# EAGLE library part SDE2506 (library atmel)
I2C/MicroWire EEPROM (24xxx)

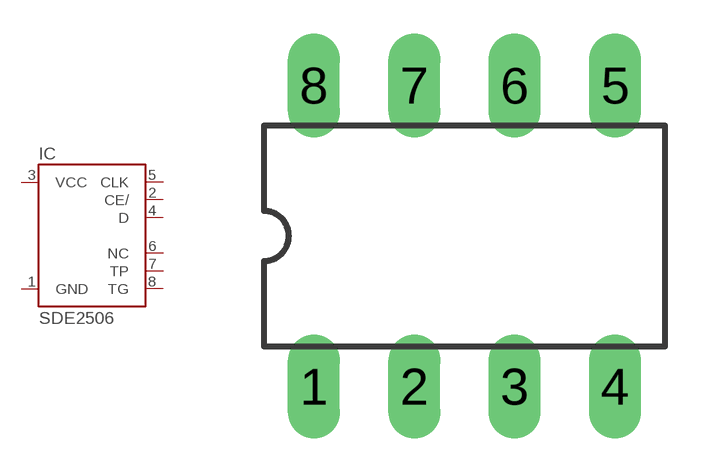
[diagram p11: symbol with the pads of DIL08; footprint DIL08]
Designator prefix IC

## SDE2506P (OC_FARNELL: unknown; OC_NEWARK: unknown)  [DIL08]
1  GND  pwr
2  CE/  in
3  VCC  pwr
4  D
5  CLK  in
6  NC  nc
7  TP  in
8  TG

## Footprint DIL08 (pad centres in mm)
Dual In Line
drill 0.813 long: 1 -3.81,-3.81; 2 -1.27,-3.81; 3 1.27,-3.81; 4 3.81,-3.81; 5 3.81,3.81; 6 1.27,3.81; 7 -1.27,3.81; 8 -3.81,3.81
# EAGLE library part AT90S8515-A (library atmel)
MICROCONTROLLER 8 Kbytes FLASH 512 bytes SRAM 512 bytes EEPROM UART

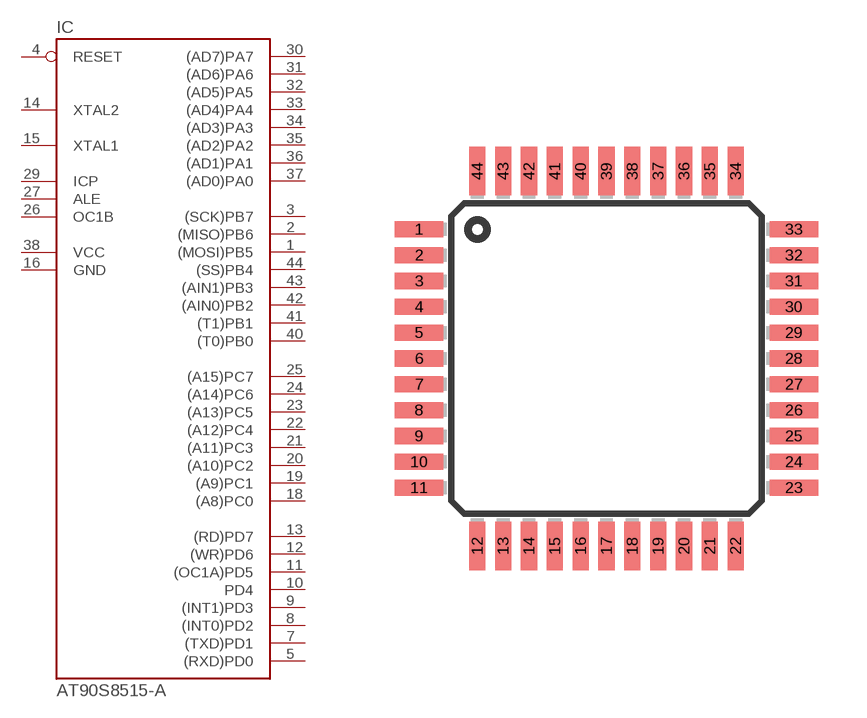
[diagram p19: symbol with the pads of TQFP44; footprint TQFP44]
Designator prefix IC

## AT90S8515-AA (OC_FARNELL: unknown; OC_NEWARK: unknown)  [TQFP44]
1  (MOSI)PB5
2  (MISO)PB6
3  (SCK)PB7
4  RESET  in
5  (RXD)PD0
6  NC1  nc
7  (TXD)PD1
8  (INT0)PD2
9  (INT1)PD3
10  PD4
11  (OC1A)PD5
12  (WR)PD6
13  (RD)PD7
14  XTAL2
15  XTAL1
16  GND  pwr
17  NC2  nc
18  (A8)PC0
19  (A9)PC1
20  (A10)PC2
21  (A11)PC3
22  (A12)PC4
23  (A13)PC5
24  (A14)PC6
25  (A15)PC7
26  OC1B
27  ALE
28  NC3  nc
29  ICP
30  (AD7)PA7
31  (AD6)PA6
32  (AD5)PA5
33  (AD4)PA4
34  (AD3)PA3
35  (AD2)PA2
36  (AD1)PA1
37  (AD0)PA0
38  VCC  pwr
39  NC4  nc
40  (T0)PB0
41  (T1)PB1
42  (AIN0)PB2
43  (AIN1)PB3
44  (SS)PB4

## Footprint TQFP44 (pad centres in mm)
44-lead Thin Quad Flat Package
smd 1.5 x 0.5: 1 -5.8,4; 2 -5.8,3.2; 3 -5.8,2.4; 4 -5.8,1.6; 5 -5.8,0.8; 6 -5.8,0; 7 -5.8,-0.8; 8 -5.8,-1.6; 9 -5.8,-2.4; 10 -5.8,-3.2; 11 -5.8,-4; 23 5.8,-4; 24 5.8,-3.2; 25 5.8,-2.4; 26 5.8,-1.6; 27 5.8,-0.8; 28 5.8,0; 29 5.8,0.8; 30 5.8,1.6; 31 5.8,2.4; 32 5.8,3.2; 33 5.8,4
smd 0.5 x 1.5: 12 -4,-5.8; 13 -3.2,-5.8; 14 -2.4,-5.8; 15 -1.6,-5.8; 16 -0.8,-5.8; 17 0,-5.8; 18 0.8,-5.8; 19 1.6,-5.8; 20 2.4,-5.8; 21 3.2,-5.8; 22 4,-5.8; 34 4,5.8; 35 3.2,5.8; 36 2.4,5.8; 37 1.6,5.8; 38 0.8,5.8; 39 0,5.8; 40 -0.8,5.8; 41 -1.6,5.8; 42 -2.4,5.8; 43 -3.2,5.8; 44 -4,5.8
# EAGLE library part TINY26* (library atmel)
8-bit AVR Microcontroller with 2K Bytes Flash Source: http://www.atmel.com .. doc1477.pdf

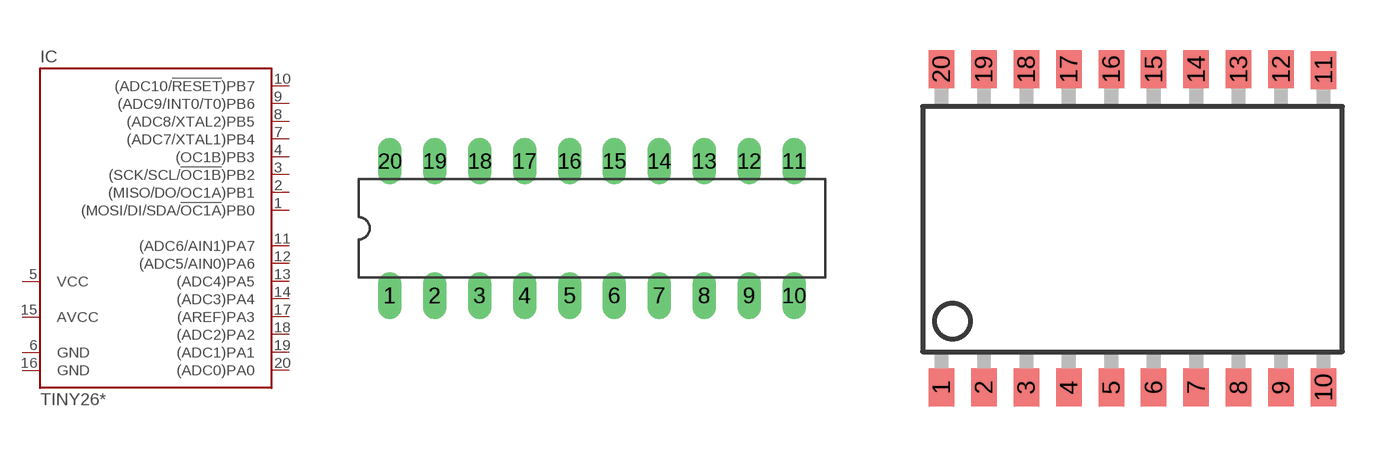
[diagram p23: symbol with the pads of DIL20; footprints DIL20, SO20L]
Designator prefix IC

## TINY26P (MPN: ATTINY261-20PU; OC_FARNELL: 1455146; OC_NEWARK: 58M3782), TINY26LP (MPN: ATTINY26L-8PU; OC_FARNELL: 9171657; OC_NEWARK: 01M6920)  [DIL20]
1  (MOSI/DI/SDA/!OC1A!)PB0
2  (MISO/DO/OC1A)PB1
3  (SCK/SCL/!OC1B!)PB2
4  (OC1B)PB3
5  VCC  pwr
6  GND  pwr
7  (ADC7/XTAL1)PB4
8  (ADC8/XTAL2)PB5
9  (ADC9/INT0/T0)PB6
10  (ADC10/!RESET!)PB7
11  (ADC6/AIN1)PA7
12  (ADC5/AIN0)PA6
13  (ADC4)PA5
14  (ADC3)PA4
15  AVCC  pwr
16  GND  pwr
17  (AREF)PA3
18  (ADC2)PA2
19  (ADC1)PA1
20  (ADC0)PA0

## TINY26S (MPN: ATTINY261-20SU; OC_FARNELL: 1455147; OC_NEWARK: 58M3783), TINY26LS (MPN: ATTINY26L-8SU; OC_FARNELL: 9171665; OC_NEWARK: 01M6921)  [SO20L]
Pads as for DIL20

## TINY26M (OC_FARNELL: unknown; OC_NEWARK: unknown), TINY26LM (OC_FARNELL: unknown; OC_NEWARK: unknown)  [MLF32]
2  (OC1B)PB3
4  VCC  pwr
5  GND  pwr
7  (ADC7/XTAL1)PB4
8  (ADC8/XTAL2)PB5
10  (ADC9/INT0/T0)PB6
11  (ADC10/!RESET!)PB7
13  (ADC6/AIN1)PA7
14  (ADC5/AIN0)PA6
15  (ADC4)PA5
17  (ADC3)PA4
18  AVCC  pwr
21  GND  pwr
22  (AREF)PA3
23  (ADC2)PA2
25  (ADC1)PA1
26  (ADC0)PA0
30  (MOSI/DI/SDA/!OC1A!)PB0
31  (MISO/DO/OC1A)PB1
32  (SCK/SCL/!OC1B!)PB2

## Footprint DIL20 (pad centres in mm)
Dual In Line
drill 0.813 long: 1 -11.43,-3.81; 2 -8.89,-3.81; 3 -6.35,-3.81; 4 -3.81,-3.81; 5 -1.27,-3.81; 6 1.27,-3.81; 7 3.81,-3.81; 8 6.35,-3.81; 9 8.89,-3.81; 10 11.43,-3.81; 11 11.43,3.81; 12 8.89,3.81; 13 6.35,3.81; 14 3.81,3.81; 15 1.27,3.81; 16 -1.27,3.81; 17 -3.81,3.81; 18 -6.35,3.81; 19 -8.89,3.81; 20 -11.43,3.81

## Footprint SO20L (pad centres in mm)
Small Outline Package SOIC 0.300"
smd 0.762 x 1.143: 1 -5.08,-5.131; 2 -3.81,-5.131; 3 -2.54,-5.131; 4 -1.27,-5.131; 5 0,-5.131; 6 1.27,-5.131; 7 2.54,-5.131; 8 3.81,-5.131; 9 5.08,-5.131; 10 6.35,-5.131; 11 6.35,4.369; 12 5.08,4.394; 13 3.81,4.394; 14 2.54,4.394; 15 1.27,4.394; 16 0,4.394; 17 -1.27,4.394; 18 -2.54,4.394; 19 -3.81,4.394; 20 -5.08,4.394

## Footprint MLF32 (pad centres in mm)
32M1-A Micro Lead Frame package (MLF)
smd 0.7 x 0.3: 1 -2.35,1.75; 2 -2.35,1.25; 3 -2.35,0.75; 4 -2.35,0.25; 5 -2.35,-0.25; 6 -2.35,-0.75; 7 -2.35,-1.25; 8 -2.35,-1.75; 17 2.35,-1.75; 18 2.35,-1.25; 19 2.35,-0.75; 20 2.35,-0.25; 21 2.35,0.25; 22 2.35,0.75; 23 2.35,1.25; 24 2.35,1.75
smd 0.3 x 0.7: 9 -1.75,-2.35; 10 -1.25,-2.35; 11 -0.75,-2.35; 12 -0.25,-2.35; 13 0.25,-2.35; 14 0.75,-2.35; 15 1.25,-2.35; 16 1.75,-2.35; 25 1.75,2.35; 26 1.25,2.35; 27 0.75,2.35; 28 0.25,2.35; 29 -0.25,2.35; 30 -0.75,2.35; 31 -1.25,2.35; 32 -1.75,2.35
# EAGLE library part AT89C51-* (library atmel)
8-bit Microcontroller with 4K Bytes Flash Not Recommended for New Designs. Use AT89S51. Source: http://www.atmel.com/dyn/resources/prod_documents/doc0265.

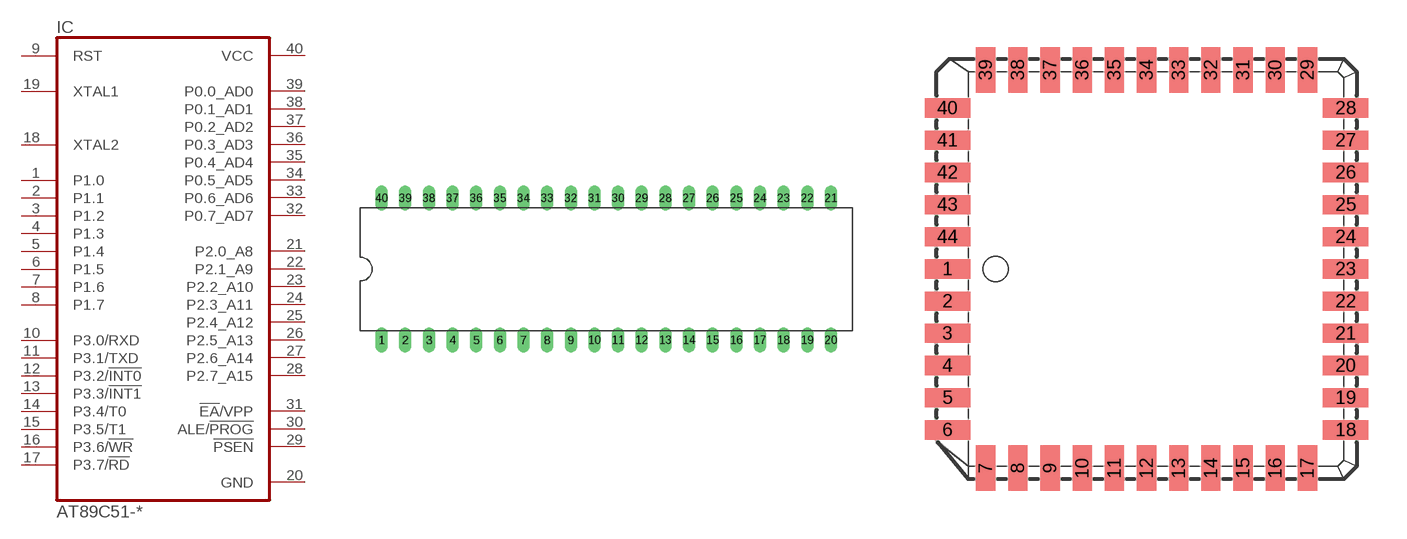
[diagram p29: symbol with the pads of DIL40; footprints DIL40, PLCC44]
Designator prefix IC

## AT89C51-12PC (OC_FARNELL: unknown; OC_NEWARK: unknown), AT89C51-16PC (OC_FARNELL: unknown; OC_NEWARK: unknown), AT89C51-20PC (OC_FARNELL: unknown; OC_NEWARK: unknown), AT89C51-24PC (OC_FARNELL: unknown; OC_NEWARK: unknown)  [DIL40]
1  P1.0
2  P1.1
3  P1.2
4  P1.3
5  P1.4
6  P1.5
7  P1.6
8  P1.7
9  RST  in
10  P3.0/RXD
11  P3.1/TXD
12  P3.2/!INT0
13  P3.3/!INT1
14  P3.4/T0
15  P3.5/T1
16  P3.6/!WR
17  P3.7/!RD
18  XTAL2  in
19  XTAL1  in
20  GND  pwr
21  P2.0_A8
22  P2.1_A9
23  P2.2_A10
24  P2.3_A11
25  P2.4_A12
26  P2.5_A13
27  P2.6_A14
28  P2.7_A15
29  !PSEN  out
30  ALE/!PROG  out
31  !EA!/VPP  in
32  P0.7_AD7
33  P0.6_AD6
34  P0.5_AD5
35  P0.4_AD4
36  P0.3_AD3
37  P0.2_AD2
38  P0.1_AD1
39  P0.0_AD0
40  VCC  pwr

## AT89C51-JC (MPN: AT89C51ED2-SLSUM; OC_FARNELL: 1095722; OC_NEWARK: 78K5790), AT89C51-12JC (MPN: AT89C51ED2-SLSUM; OC_FARNELL: 1095722; OC_NEWARK: 78K5790), AT89C51-16JC (MPN: AT89C51RE2-SLSUM; OC_FARNELL: 1455062; OC_NEWARK: 58M3857), AT89C51-20JC (MPN: AT89C51ED2-RLTUM; OC_FARNELL: 1095726; OC_NEWARK: 51P1802), AT89C51-24JC (MPN: AT89C51ED2-SLSUM; OC_FARNELL: 1095722; OC_NEWARK: 78K5790)  [PLCC44]
2  P1.0
3  P1.1
4  P1.2
5  P1.3
6  P1.4
7  P1.5
8  P1.6
9  P1.7
10  RST  in
11  P3.0/RXD
13  P3.1/TXD
14  P3.2/!INT0
15  P3.3/!INT1
16  P3.4/T0
17  P3.5/T1
18  P3.6/!WR
19  P3.7/!RD
20  XTAL2  in
21  XTAL1  in
22  GND  pwr
24  P2.0_A8
25  P2.1_A9
26  P2.2_A10
27  P2.3_A11
28  P2.4_A12
29  P2.5_A13
30  P2.6_A14
31  P2.7_A15
32  !PSEN  out
33  ALE/!PROG  out
35  !EA!/VPP  in
36  P0.7_AD7
37  P0.6_AD6
38  P0.5_AD5
39  P0.4_AD4
40  P0.3_AD3
41  P0.2_AD2
42  P0.1_AD1
43  P0.0_AD0
44  VCC  pwr

## Footprint DIL40 (pad centres in mm)
Dual In Line
drill 0.813 long: 1 -24.13,-7.62; 2 -21.59,-7.62; 3 -19.05,-7.62; 4 -16.51,-7.62; 5 -13.97,-7.62; 6 -11.43,-7.62; 7 -8.89,-7.62; 8 -6.35,-7.62; 9 -3.81,-7.62; 10 -1.27,-7.62; 11 1.27,-7.62; 12 3.81,-7.62; 13 6.35,-7.62; 14 8.89,-7.62; 15 11.43,-7.62; 16 13.97,-7.62; 17 16.51,-7.62; 18 19.05,-7.62; 19 21.59,-7.62; 20 24.13,-7.62; 21 24.13,7.62; 22 21.59,7.62; 23 19.05,7.62; 24 16.51,7.62; 25 13.97,7.62; 26 11.43,7.62; 27 8.89,7.62; 28 6.35,7.62; 29 3.81,7.62; 30 1.27,7.62; 31 -1.27,7.62; 32 -3.81,7.62; 33 -6.35,7.62; 34 -8.89,7.62; 35 -11.43,7.62; 36 -13.97,7.62; 37 -16.51,7.62; 38 -19.05,7.62; 39 -21.59,7.62; 40 -24.13,7.62

## Footprint PLCC44 (pad centres in mm)
Plastic J-Leaded Chip Carrier
smd 1.8 x 0.76: 1 -7.86,0; 2 -7.86,-1.27; 3 -7.86,-2.54; 4 -7.86,-3.81; 5 -7.86,-5.08; 6 -7.86,-6.35; 18 7.86,-6.35; 19 7.86,-5.08; 20 7.86,-3.81; 21 7.86,-2.54; 22 7.86,-1.27; 23 7.86,0; 24 7.86,1.27; 25 7.86,2.54; 26 7.86,3.81; 27 7.86,5.08; 28 7.86,6.35; 40 -7.86,6.35; 41 -7.86,5.08; 42 -7.86,3.81; 43 -7.86,2.54; 44 -7.86,1.27
smd 0.76 x 1.8: 7 -6.35,-7.86; 8 -5.08,-7.86; 9 -3.81,-7.86; 10 -2.54,-7.86; 11 -1.27,-7.86; 12 0,-7.86; 13 1.27,-7.86; 14 2.54,-7.86; 15 3.81,-7.86; 16 5.08,-7.86; 17 6.35,-7.86; 29 6.35,7.86; 30 5.08,7.86; 31 3.81,7.86; 32 2.54,7.86; 33 1.27,7.86; 34 0,7.86; 35 -1.27,7.86; 36 -2.54,7.86; 37 -3.81,7.86; 38 -5.08,7.86; 39 -6.35,7.86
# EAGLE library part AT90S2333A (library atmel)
MICROCONTROLLER 2 Kbytes FLASH 128 bytes SRAM 128 bytes EEPROM UART 6-channel 10-bit ADC

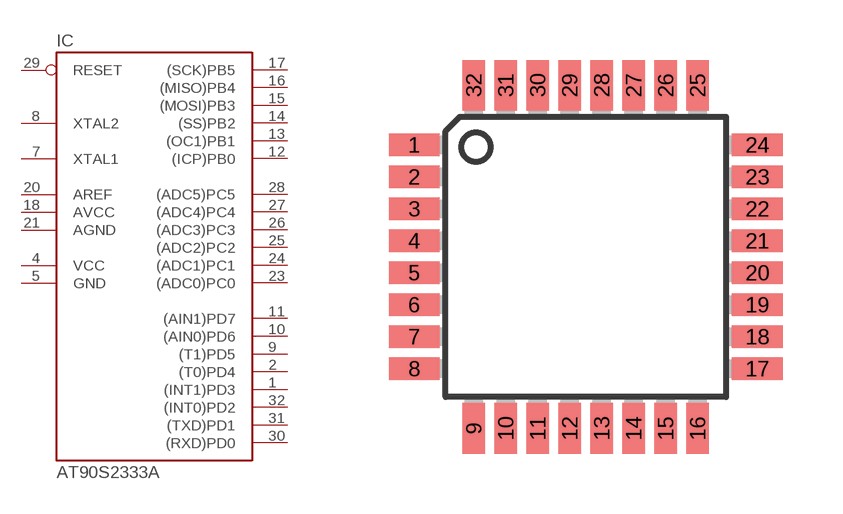
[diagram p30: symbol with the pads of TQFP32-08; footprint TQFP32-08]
Designator prefix IC

## AT90S2333AA (OC_FARNELL: unknown; OC_NEWARK: unknown)  [TQFP32-08]
1  (INT1)PD3
2  (T0)PD4
3  NC1  nc
4  VCC  pwr
5  GND  pwr
6  NC2  nc
7  XTAL1
8  XTAL2
9  (T1)PD5
10  (AIN0)PD6
11  (AIN1)PD7
12  (ICP)PB0
13  (OC1)PB1
14  (SS)PB2
15  (MOSI)PB3
16  (MISO)PB4
17  (SCK)PB5
18  AVCC  pwr
19  NC3  nc
20  AREF  pas
21  AGND  pwr
22  NC4  nc
23  (ADC0)PC0
24  (ADC1)PC1
25  (ADC2)PC2
26  (ADC3)PC3
27  (ADC4)PC4
28  (ADC5)PC5
29  RESET  in
30  (RXD)PD0
31  (TXD)PD1
32  (INT0)PD2

## Footprint TQFP32-08 (pad centres in mm)
Thin Plasic Quad Flat Package Grid 0.8 mm
smd 1.27 x 0.559: 1 -4.293,2.8; 2 -4.293,2; 3 -4.293,1.2; 4 -4.293,0.4; 5 -4.293,-0.4; 6 -4.293,-1.2; 7 -4.293,-2; 8 -4.293,-2.8; 17 4.293,-2.8; 18 4.293,-2; 19 4.293,-1.2; 20 4.293,-0.4; 21 4.293,0.4; 22 4.293,1.2; 23 4.293,2; 24 4.293,2.8
smd 0.559 x 1.27: 9 -2.8,-4.293; 10 -2,-4.293; 11 -1.2,-4.293; 12 -0.4,-4.293; 13 0.4,-4.293; 14 1.2,-4.293; 15 2,-4.293; 16 2.8,-4.293; 25 2.8,4.293; 26 2,4.293; 27 1.2,4.293; 28 0.4,4.293; 29 -0.4,4.293; 30 -1.2,4.293; 31 -2,4.293; 32 -2.8,4.293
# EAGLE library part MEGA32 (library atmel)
MICROCONTROLLER 32 Kbytes FLASH 2 Kbytes SRAM 1 Kbytes EEPROM USART 8-channel 10 bit ADC Source: www.atmel.com .. doc2503.pdf

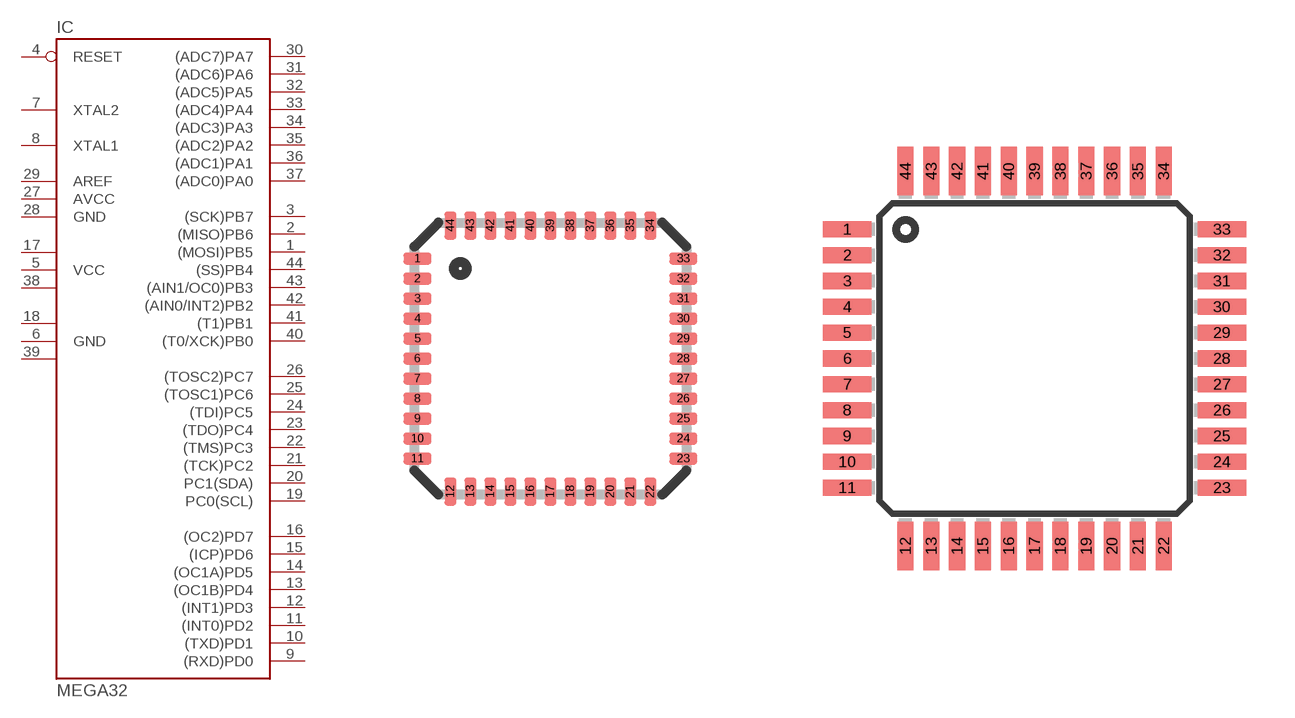
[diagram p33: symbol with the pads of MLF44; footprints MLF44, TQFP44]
Designator prefix IC

## MEGA32-M (MPN: ATMEGA32-16MU; OC_FARNELL: 1455108; OC_NEWARK: 58M3733)  [MLF44]
1  (MOSI)PB5
2  (MISO)PB6
3  (SCK)PB7
4  RESET  in
5  VCC  pwr
6  GND  pwr
7  XTAL2
8  XTAL1
9  (RXD)PD0
10  (TXD)PD1
11  (INT0)PD2
12  (INT1)PD3
13  (OC1B)PD4
14  (OC1A)PD5
15  (ICP)PD6
16  (OC2)PD7
17  VCC1  pwr
18  GND1  pwr
19  PC0(SCL)
20  PC1(SDA)
21  (TCK)PC2
22  (TMS)PC3
23  (TDO)PC4
24  (TDI)PC5
25  (TOSC1)PC6
26  (TOSC2)PC7
27  AVCC  pwr
28  GND  pwr
29  AREF  pas
30  (ADC7)PA7
31  (ADC6)PA6
32  (ADC5)PA5
33  (ADC4)PA4
34  (ADC3)PA3
35  (ADC2)PA2
36  (ADC1)PA1
37  (ADC0)PA0
38  VCC2  pwr
39  GND2  pwr
40  (T0/XCK)PB0
41  (T1)PB1
42  (AIN0/INT2)PB2
43  (AIN1/OC0)PB3
44  (SS)PB4

## MEGA32-A (MPN: ATMEGA32-16AU; OC_FARNELL: 9171274; OC_NEWARK: 69K6677)  [TQFP44]
Pads as for MLF44

## Footprint MLF44 (pad centres in mm)
44M1 Micro Lead Frame package (MLF)
smd 0.7 x 0.3: 1 -3.325,2.5; 2 -3.325,2; 3 -3.325,1.5; 4 -3.325,1; 5 -3.325,0.5; 6 -3.325,0; 7 -3.325,-0.5; 8 -3.325,-1; 9 -3.325,-1.5; 10 -3.325,-2; 11 -3.325,-2.5; 23 3.325,-2.5; 24 3.325,-2; 25 3.325,-1.5; 26 3.325,-1; 27 3.325,-0.5; 28 3.325,0; 29 3.325,0.5; 30 3.325,1; 31 3.325,1.5; 32 3.325,2; 33 3.325,2.5
smd 0.3 x 0.7: 12 -2.5,-3.325; 13 -2,-3.325; 14 -1.5,-3.325; 15 -1,-3.325; 16 -0.5,-3.325; 17 0,-3.325; 18 0.5,-3.325; 19 1,-3.325; 20 1.5,-3.325; 21 2,-3.325; 22 2.5,-3.325; 34 2.5,3.325; 35 2,3.325; 36 1.5,3.325; 37 1,3.325; 38 0.5,3.325; 39 0,3.325; 40 -0.5,3.325; 41 -1,3.325; 42 -1.5,3.325; 43 -2,3.325; 44 -2.5,3.325

## Footprint TQFP44 (pad centres in mm)
44-lead Thin Quad Flat Package
smd 1.5 x 0.5: 1 -5.8,4; 2 -5.8,3.2; 3 -5.8,2.4; 4 -5.8,1.6; 5 -5.8,0.8; 6 -5.8,0; 7 -5.8,-0.8; 8 -5.8,-1.6; 9 -5.8,-2.4; 10 -5.8,-3.2; 11 -5.8,-4; 23 5.8,-4; 24 5.8,-3.2; 25 5.8,-2.4; 26 5.8,-1.6; 27 5.8,-0.8; 28 5.8,0; 29 5.8,0.8; 30 5.8,1.6; 31 5.8,2.4; 32 5.8,3.2; 33 5.8,4
smd 0.5 x 1.5: 12 -4,-5.8; 13 -3.2,-5.8; 14 -2.4,-5.8; 15 -1.6,-5.8; 16 -0.8,-5.8; 17 0,-5.8; 18 0.8,-5.8; 19 1.6,-5.8; 20 2.4,-5.8; 21 3.2,-5.8; 22 4,-5.8; 34 4,5.8; 35 3.2,5.8; 36 2.4,5.8; 37 1.6,5.8; 38 0.8,5.8; 39 0,5.8; 40 -0.8,5.8; 41 -1.6,5.8; 42 -2.4,5.8; 43 -3.2,5.8; 44 -4,5.8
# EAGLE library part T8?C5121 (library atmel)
8-bit Microcontroller with Multiprotocol Smart Card Interface Source: http://www.atmel.com/...doc4164.pdf

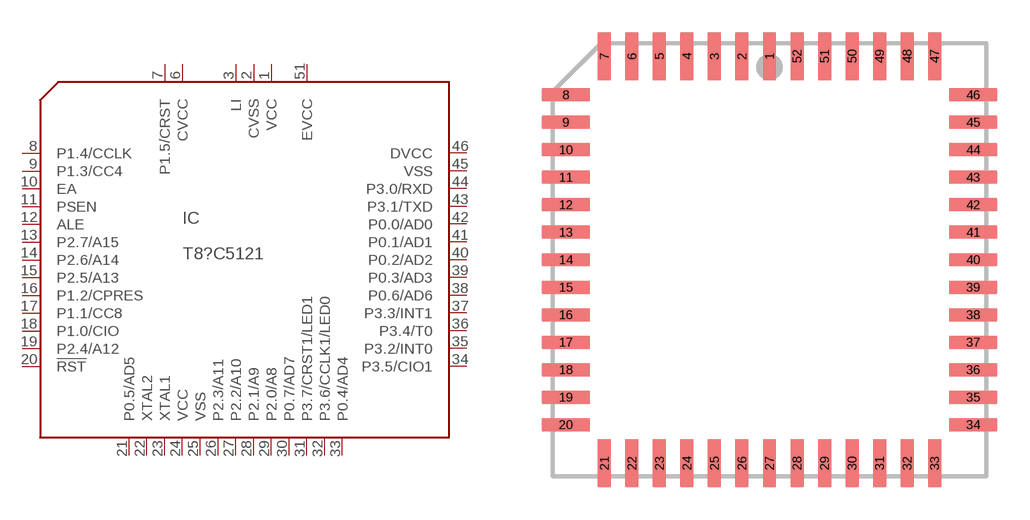
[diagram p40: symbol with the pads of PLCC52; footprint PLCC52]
Designator prefix IC

## T83C5121 (OC_FARNELL: unknown; OC_NEWARK: unknown)  [PLCC52]
1  VCC  pwr
2  CVSS  pwr
3  LI  pwr
6  CVCC  pwr
7  P1.5/CRST
8  P1.4/CCLK
9  P1.3/CC4
10  EA
11  PSEN
12  ALE
13  P2.7/A15
14  P2.6/A14
15  P2.5/A13
16  P1.2/CPRES
17  P1.1/CC8
18  P1.0/CIO
19  P2.4/A12
20  !RST
21  P0.5/AD5
22  XTAL2  in
23  XTAL1  out
24  VCC  pwr
25  VSS  pwr
26  P2.3/A11
27  P2.2/A10
28  P2.1/A9
29  P2.0/A8
30  P0.7/AD7
31  P3.7/CRST1/LED1
32  P3.6/CCLK1/LED0
33  P0.4/AD4
34  P3.5/CIO1
35  P3.2/INT0
36  P3.4/T0
37  P3.3/INT1
38  P0.6/AD6
39  P0.3/AD3
40  P0.2/AD2
41  P0.1/AD1
42  P0.0/AD0
43  P3.1/TXD
44  P3.0/RXD
45  VSS  pwr
46  DVCC  pwr
51  EVCC  pas

## T85C5121 (OC_FARNELL: unknown; OC_NEWARK: unknown)  [PLCC52]
Pads as for PLCC52

## T89C5121 (OC_FARNELL: unknown; OC_NEWARK: unknown)  [PLCC52]
Pads as for PLCC52

## Footprint PLCC52 (pad centres in mm)
PLASTIC LEADED CHIP CARRIER square
smd 0.6 x 2.2: 1 0,9.4; 2 -1.27,9.4; 3 -2.54,9.4; 4 -3.81,9.4; 5 -5.08,9.4; 6 -6.35,9.4; 7 -7.62,9.4; 21 -7.62,-9.4; 22 -6.35,-9.4; 23 -5.08,-9.4; 24 -3.81,-9.4; 25 -2.54,-9.4; 26 -1.27,-9.4; 27 0,-9.4; 28 1.27,-9.4; 29 2.54,-9.4; 30 3.81,-9.4; 31 5.08,-9.4; 32 6.35,-9.4; 33 7.62,-9.4; 47 7.62,9.4; 48 6.35,9.4; 49 5.08,9.4; 50 3.81,9.4; 51 2.54,9.4; 52 1.27,9.4
smd 2.2 x 0.6: 8 -9.4,7.62; 9 -9.4,6.35; 10 -9.4,5.08; 11 -9.4,3.81; 12 -9.4,2.54; 13 -9.4,1.27; 14 -9.4,0; 15 -9.4,-1.27; 16 -9.4,-2.54; 17 -9.4,-3.81; 18 -9.4,-5.08; 19 -9.4,-6.35; 20 -9.4,-7.62; 34 9.4,-7.62; 35 9.4,-6.35; 36 9.4,-5.08; 37 9.4,-3.81; 38 9.4,-2.54; 39 9.4,-1.27; 40 9.4,0; 41 9.4,1.27; 42 9.4,2.54; 43 9.4,3.81; 44 9.4,5.08; 45 9.4,6.35; 46 9.4,7.62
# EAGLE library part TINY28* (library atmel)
MICROCONTROLLER 1.8 V 2 Kbytes FLASH

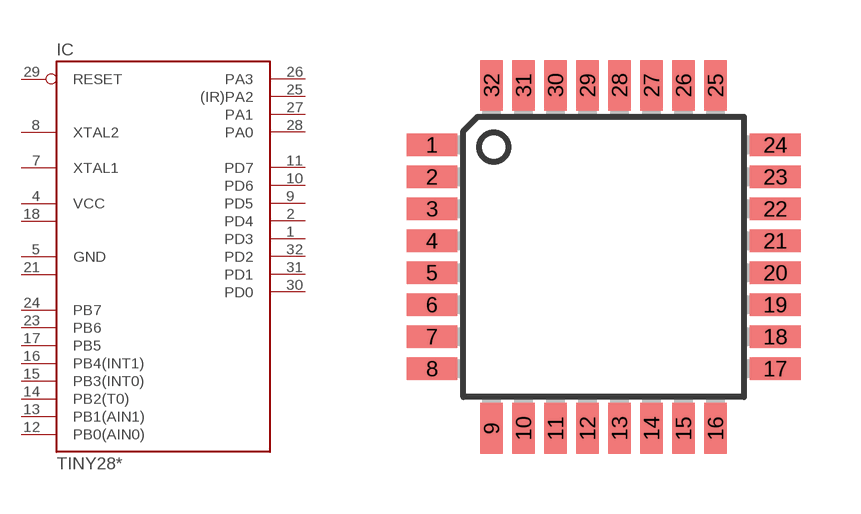
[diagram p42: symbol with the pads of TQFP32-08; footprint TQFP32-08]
Designator prefix IC

## TINY28LA (OC_FARNELL: unknown; OC_NEWARK: unknown), TINY28VA (OC_FARNELL: unknown; OC_NEWARK: unknown)  [TQFP32-08]
1  PD3
2  PD4
3  NC1  nc
4  VCC  pwr
5  GND  pwr
6  NC2  nc
7  XTAL1
8  XTAL2
9  PD5
10  PD6
11  PD7
12  PB0(AIN0)  in
13  PB1(AIN1)  in
14  PB2(T0)  in
15  PB3(INT0)  in
16  PB4(INT1)  in
17  PB5  in
18  VCC1  pwr
19  NC3  nc
20  NC4  nc
21  GND1  pwr
22  NC5  nc
23  PB6  in
24  PB7  in
25  (IR)PA2  out
26  PA3
27  PA1
28  PA0
29  RESET  in
30  PD0
31  PD1
32  PD2

## Footprint TQFP32-08 (pad centres in mm)
Thin Plasic Quad Flat Package Grid 0.8 mm
smd 1.27 x 0.559: 1 -4.293,2.8; 2 -4.293,2; 3 -4.293,1.2; 4 -4.293,0.4; 5 -4.293,-0.4; 6 -4.293,-1.2; 7 -4.293,-2; 8 -4.293,-2.8; 17 4.293,-2.8; 18 4.293,-2; 19 4.293,-1.2; 20 4.293,-0.4; 21 4.293,0.4; 22 4.293,1.2; 23 4.293,2; 24 4.293,2.8
smd 0.559 x 1.27: 9 -2.8,-4.293; 10 -2,-4.293; 11 -1.2,-4.293; 12 -0.4,-4.293; 13 0.4,-4.293; 14 1.2,-4.293; 15 2,-4.293; 16 2.8,-4.293; 25 2.8,4.293; 26 2,4.293; 27 1.2,4.293; 28 0.4,4.293; 29 -0.4,4.293; 30 -1.2,4.293; 31 -2,4.293; 32 -2.8,4.293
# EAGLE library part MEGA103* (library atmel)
MICROCONTROLLER Low-voltage (L) 128 Kbytes FLASH 4 Kbytes SRAM 2 Kbytes EEPROM UART RTC 8-channel 10 bit ADC Source: avr.lbr

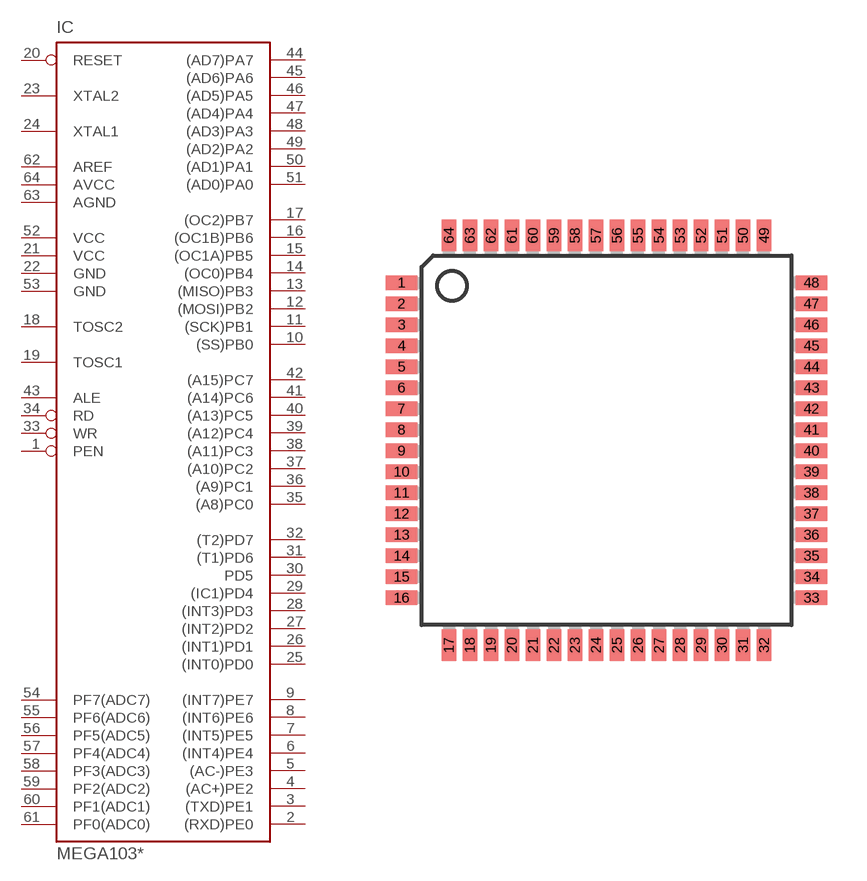
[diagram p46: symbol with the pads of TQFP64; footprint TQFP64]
Designator prefix IC

## MEGA103 (OC_FARNELL: unknown; OC_NEWARK: unknown), MEGA103L (OC_FARNELL: unknown; OC_NEWARK: unknown)  [TQFP64]
1  PEN  in
2  (RXD)PE0
3  (TXD)PE1
4  (AC+)PE2
5  (AC-)PE3
6  (INT4)PE4
7  (INT5)PE5
8  (INT6)PE6
9  (INT7)PE7
10  (SS)PB0
11  (SCK)PB1
12  (MOSI)PB2
13  (MISO)PB3
14  (OC0)PB4
15  (OC1A)PB5
16  (OC1B)PB6
17  (OC2)PB7
18  TOSC2
19  TOSC1
20  RESET  in
21  VCC  pwr
22  GND  pwr
23  XTAL2
24  XTAL1
25  (INT0)PD0
26  (INT1)PD1
27  (INT2)PD2
28  (INT3)PD3
29  (IC1)PD4
30  PD5
31  (T1)PD6
32  (T2)PD7
33  WR
34  RD
35  (A8)PC0  out
36  (A9)PC1  out
37  (A10)PC2  out
38  (A11)PC3  out
39  (A12)PC4  out
40  (A13)PC5  out
41  (A14)PC6  out
42  (A15)PC7  out
43  ALE
44  (AD7)PA7
45  (AD6)PA6
46  (AD5)PA5
47  (AD4)PA4
48  (AD3)PA3
49  (AD2)PA2
50  (AD1)PA1
51  (AD0)PA0
52  VCC  pwr
53  GND  pwr
54  PF7(ADC7)  in
55  PF6(ADC6)  in
56  PF5(ADC5)  in
57  PF4(ADC4)  in
58  PF3(ADC3)  in
59  PF2(ADC2)  in
60  PF1(ADC1)  in
61  PF0(ADC0)  in
62  AREF  pas
63  AGND  pwr
64  AVCC  pwr

## Footprint TQFP64 (pad centres in mm)
Thin Plasic Quad Flat Package Updated from atml.lbr 17.01.2005 alf@cadsoft.de
smd 1.194 x 0.559: 1 -7.8,6; 2 -7.8,5.2; 3 -7.8,4.4; 4 -7.8,3.6; 5 -7.8,2.8; 6 -7.8,2; 7 -7.8,1.2; 8 -7.8,0.4; 9 -7.8,-0.4; 10 -7.8,-1.2; 11 -7.8,-2; 12 -7.8,-2.8; 13 -7.8,-3.6; 14 -7.8,-4.4; 15 -7.8,-5.2; 16 -7.8,-6; 33 7.8,-6; 34 7.8,-5.2; 35 7.8,-4.4; 36 7.8,-3.6; 37 7.8,-2.8; 38 7.8,-2; 39 7.8,-1.2; 40 7.8,-0.4; 41 7.8,0.4; 42 7.8,1.2; 43 7.8,2; 44 7.8,2.8; 45 7.8,3.6; 46 7.8,4.4; 47 7.8,5.2; 48 7.8,6
smd 0.559 x 1.194: 17 -6,-7.8; 18 -5.2,-7.8; 19 -4.4,-7.8; 20 -3.6,-7.8; 21 -2.8,-7.8; 22 -2,-7.8; 23 -1.2,-7.8; 24 -0.4,-7.8; 25 0.4,-7.8; 26 1.2,-7.8; 27 2,-7.8; 28 2.8,-7.8; 29 3.6,-7.8; 30 4.4,-7.8; 31 5.2,-7.8; 32 6,-7.8; 49 6,7.8; 50 5.2,7.8; 51 4.4,7.8; 52 3.6,7.8; 53 2.8,7.8; 54 2,7.8; 55 1.2,7.8; 56 0.4,7.8; 57 -0.4,7.8; 58 -1.2,7.8; 59 -2,7.8; 60 -2.8,7.8; 61 -3.6,7.8; 62 -4.4,7.8; 63 -5.2,7.8; 64 -6,7.8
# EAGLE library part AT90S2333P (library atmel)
MICROCONTROLLER 2 Kbytes FLASH 128 bytes SRAM 128 bytes EEPROM UART 6-channel 10-bit ADC

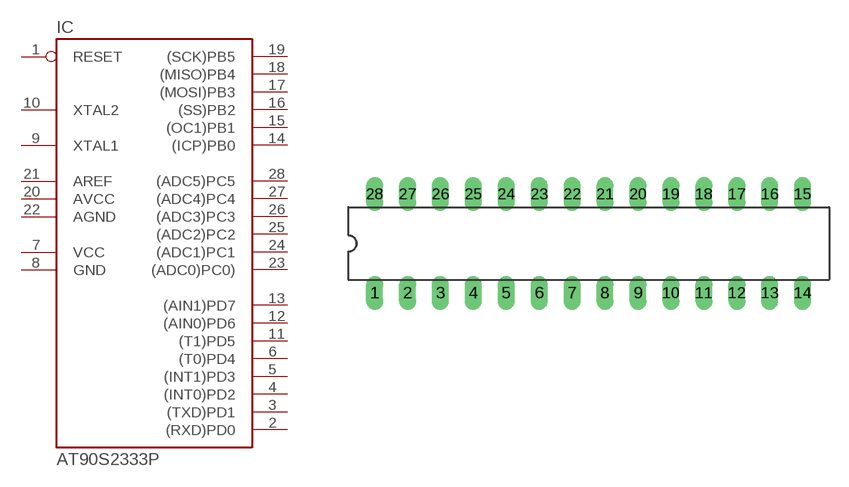
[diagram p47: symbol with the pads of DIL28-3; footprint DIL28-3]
Designator prefix IC

## AT90S2333P (OC_FARNELL: unknown; OC_NEWARK: unknown)  [DIL28-3]
1  RESET  in
2  (RXD)PD0
3  (TXD)PD1
4  (INT0)PD2
5  (INT1)PD3
6  (T0)PD4
7  VCC  pwr
8  GND  pwr
9  XTAL1
10  XTAL2
11  (T1)PD5
12  (AIN0)PD6
13  (AIN1)PD7
14  (ICP)PB0
15  (OC1)PB1
16  (SS)PB2
17  (MOSI)PB3
18  (MISO)PB4
19  (SCK)PB5
20  AVCC  pwr
21  AREF  pas
22  AGND  pwr
23  (ADC0)PC0)
24  (ADC1)PC1
25  (ADC2)PC2
26  (ADC3)PC3
27  (ADC4)PC4
28  (ADC5)PC5

## Footprint DIL28-3 (pad centres in mm)
Dual In Line 0.3 inch
drill 0.813 long: 1 -16.51,-3.81; 2 -13.97,-3.81; 3 -11.43,-3.81; 4 -8.89,-3.81; 5 -6.35,-3.81; 6 -3.81,-3.81; 7 -1.27,-3.81; 8 1.27,-3.81; 9 3.81,-3.81; 10 6.35,-3.81; 11 8.89,-3.81; 12 11.43,-3.81; 13 13.97,-3.81; 14 16.51,-3.81; 15 16.51,3.81; 16 13.97,3.81; 17 11.43,3.81; 18 8.89,3.81; 19 6.35,3.81; 20 3.81,3.81; 21 1.27,3.81; 22 -1.27,3.81; 23 -3.81,3.81; 24 -6.35,3.81; 25 -8.89,3.81; 26 -11.43,3.81; 27 -13.97,3.81; 28 -16.51,3.81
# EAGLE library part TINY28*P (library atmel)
MICROCONTROLLER 1.8 V 2 Kbytes FLASH

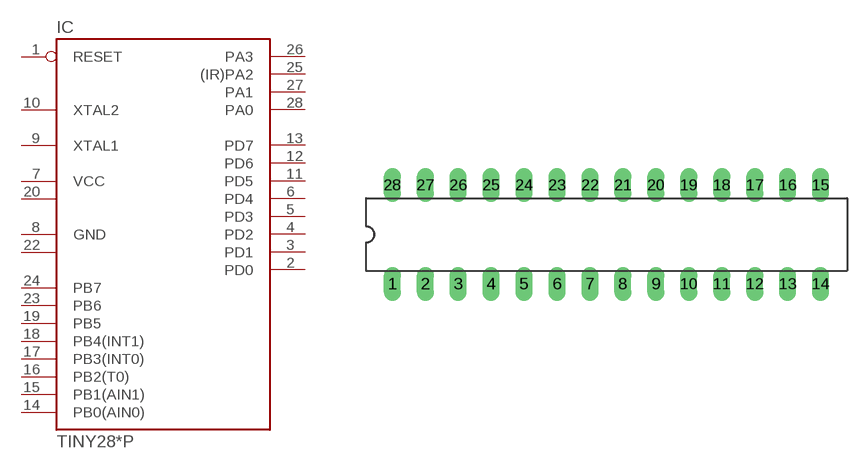
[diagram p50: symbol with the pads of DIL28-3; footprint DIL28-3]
Designator prefix IC

## TINY28LP (OC_FARNELL: unknown; OC_NEWARK: unknown), TINY28VP (OC_FARNELL: unknown; OC_NEWARK: unknown)  [DIL28-3]
1  RESET  in
2  PD0
3  PD1
4  PD2
5  PD3
6  PD4
7  VCC  pwr
8  GND  pwr
9  XTAL1
10  XTAL2
11  PD5
12  PD6
13  PD7
14  PB0(AIN0)  in
15  PB1(AIN1)  in
16  PB2(T0)  in
17  PB3(INT0)  in
18  PB4(INT1)  in
19  PB5  in
20  VCC1  pwr
21  NC1  nc
22  GND1  pwr
23  PB6  in
24  PB7  in
25  (IR)PA2  out
26  PA3
27  PA1
28  PA0

## Footprint DIL28-3 (pad centres in mm)
Dual In Line 0.3 inch
drill 0.813 long: 1 -16.51,-3.81; 2 -13.97,-3.81; 3 -11.43,-3.81; 4 -8.89,-3.81; 5 -6.35,-3.81; 6 -3.81,-3.81; 7 -1.27,-3.81; 8 1.27,-3.81; 9 3.81,-3.81; 10 6.35,-3.81; 11 8.89,-3.81; 12 11.43,-3.81; 13 13.97,-3.81; 14 16.51,-3.81; 15 16.51,3.81; 16 13.97,3.81; 17 11.43,3.81; 18 8.89,3.81; 19 6.35,3.81; 20 3.81,3.81; 21 1.27,3.81; 22 -1.27,3.81; 23 -3.81,3.81; 24 -6.35,3.81; 25 -8.89,3.81; 26 -11.43,3.81; 27 -13.97,3.81; 28 -16.51,3.81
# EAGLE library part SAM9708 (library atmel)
128-voice Integrated Sound Synthesizer

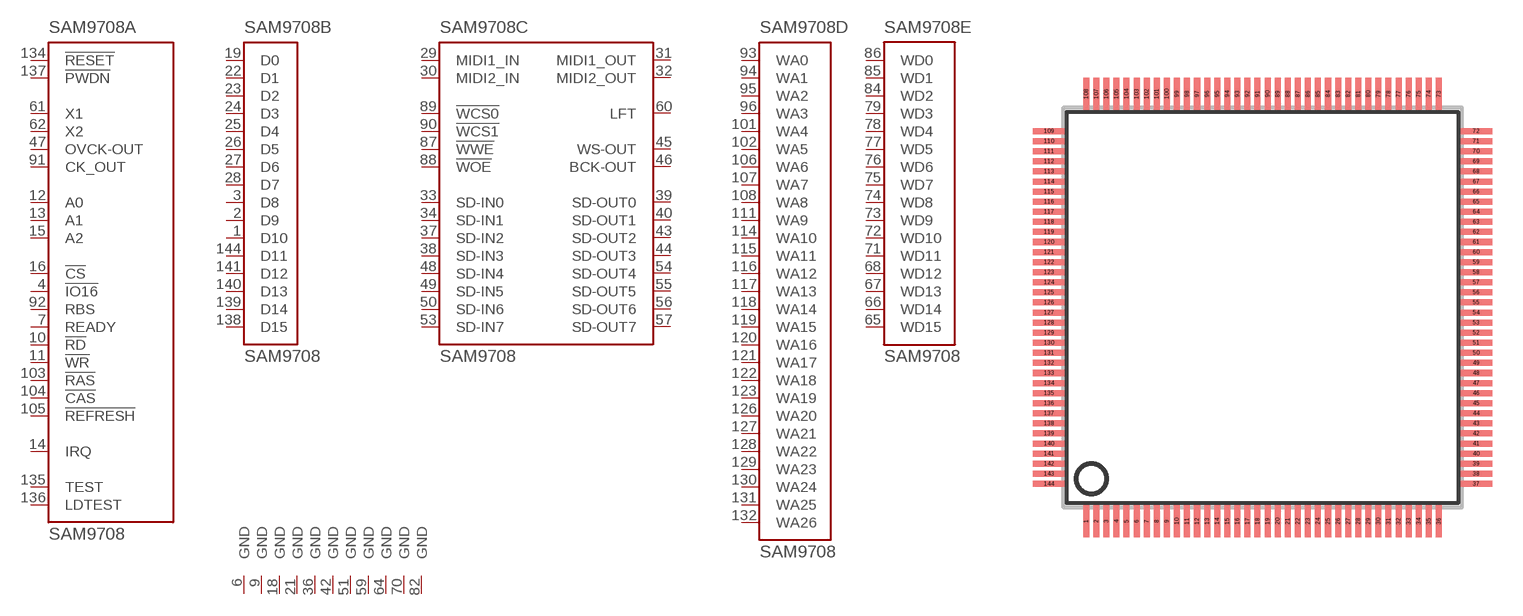
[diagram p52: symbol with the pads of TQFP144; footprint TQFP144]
Designator prefix SAM9708; gates A=SAM9708 C=SAM9708-SND B=D0-15 D=WA27 E=WD15 G1=GND G2=GND G3=GND G4=GND G5=GND G6=GND G7=GND G8=GND G9=GND G10=GND G11=GND G12=GND G13=GND G14=GND G15=GND G16=GND G17=GND G18=GND G19=GND V1=VCC1 V2=VCC1 V3=VCC1 V4=VCC1 V5=VCC1 V6=VCC2 V7=VCC2 V8=VCC2 V9=VCC2 V10=VCC2 V11=VC3 V12=VC3 V13=VC3 V14=VC3 V15=VC3 V16=VC3 V17=VC3 V18=VC3

## SAM9708 (OC_FARNELL: unknown; OC_NEWARK: unknown)  [TQFP144]
1  B:D10  hiz
2  B:D9  hiz
3  B:D8  hiz
4  A:!IO16  hiz
5  V1:VCC1  pwr
6  G1:GND  pwr
7  A:READY  hiz
8  V11:VC3  pwr
9  G2:GND  pwr
10  A:!RD  in
11  A:!WR  in
12  A:A0  in
13  A:A1  in
14  A:IRQ  hiz
15  A:A2  in
16  A:!CS  in
17  V12:VC3  pwr
18  G3:GND  pwr
19  B:D0  hiz
20  V2:VCC1  pwr
21  G4:GND  pwr
22  B:D1  hiz
23  B:D2  hiz
24  B:D3  hiz
25  B:D4  hiz
26  B:D5  hiz
27  B:D6  hiz
28  B:D7  hiz
29  C:MIDI1_IN  in
30  C:MIDI2_IN  in
31  C:MIDI1_OUT  in
32  C:MIDI2_OUT  in
33  C:SD-IN0
34  C:SD-IN1
35  V3:VCC1  pwr
36  G5:GND  pwr
37  C:SD-IN2
38  C:SD-IN3
39  C:SD-OUT0  out
40  C:SD-OUT1  out
41  V13:VC3  pwr
42  G6:GND  pwr
43  C:SD-OUT2  out
44  C:SD-OUT3  out
45  C:WS-OUT  out
46  C:BCK-OUT  out
47  A:OVCK-OUT  out
48  C:SD-IN4
49  C:SD-IN5
50  C:SD-IN6
51  G7:GND  pwr
52  V4:VCC1  pwr
53  C:SD-IN7
54  C:SD-OUT4  out
55  C:SD-OUT5  out
56  C:SD-OUT6  out
57  C:SD-OUT7  out
58  V14:VC3  pwr
59  G8:GND  pwr
60  C:LFT  pas
61  A:X1  out
62  A:X2  in
63  V15:VC3  pwr
64  G9:GND  pwr
65  E:WD15
66  E:WD14
67  E:WD13
68  E:WD12
69  V6:VCC2  pwr
70  G10:GND  pwr
71  E:WD11
72  E:WD10
73  E:WD9
74  E:WD8
75  E:WD7
76  E:WD6
77  E:WD5
78  E:WD4
79  E:WD3
80  V16:VC3  pwr
81  V7:VCC2  pwr
82  G11:GND  pwr
83  G12:GND  pwr
84  E:WD2
85  E:WD1
86  E:WD0
87  C:!WWE  out
88  C:!WOE  out
89  C:!WCS0  out
90  C:!WCS1  out
91  A:CK_OUT  out
92  A:RBS  out
93  D:WA0  out
94  D:WA1  out
95  D:WA2  out
96  D:WA3  out
97  V8:VCC2  pwr
98  G13:GND  pwr
99  V17:VC3  pwr
100  G14:GND  pwr
101  D:WA4  out
102  D:WA5  out
103  A:!RAS
104  A:!CAS
105  A:!REFRESH
106  D:WA6  out
107  D:WA7  out
108  D:WA8  out
109  V9:VCC2  pwr
110  G15:GND  pwr
111  D:WA9  out
112  V18:VC3  pwr
113  G16:GND  pwr
114  D:WA10  out
115  D:WA11  out
116  D:WA12  out
117  D:WA13  out
118  D:WA14  out
119  D:WA15  out
120  D:WA16  out
121  D:WA17  out
122  D:WA18  out
123  D:WA19  out
124  V10:VCC2  pwr
125  G17:GND  pwr
126  D:WA20  out
127  D:WA21  out
128  D:WA22  out
129  D:WA23  out
130  D:WA24  out
131  D:WA25  out
132  D:WA26  out
133  G18:GND  pwr
134  A:!RESET  in
135  A:TEST  in
136  A:LDTEST  in
137  A:!PWDN  in
138  B:D15  hiz
139  B:D14  hiz
140  B:D13  hiz
141  B:D12  hiz
142  V5:VCC1  pwr
143  G19:GND  pwr
144  B:D11  hiz

## Footprint TQFP144 (pad centres in mm)
QFP144 shrink quad flat pack, square (smd-ipc)
smd 0.3 x 1.6: 1 -8.75,-10.6; 2 -8.25,-10.6; 3 -7.75,-10.6; 4 -7.25,-10.6; 5 -6.75,-10.6; 6 -6.25,-10.6; 7 -5.75,-10.6; 8 -5.25,-10.6; 9 -4.75,-10.6; 10 -4.25,-10.6; 11 -3.75,-10.6; 12 -3.25,-10.6; 13 -2.75,-10.6; 14 -2.25,-10.6; 15 -1.75,-10.6; 16 -1.25,-10.6; 17 -0.75,-10.6; 18 -0.25,-10.6; 19 0.25,-10.6; 20 0.75,-10.6; 21 1.25,-10.6; 22 1.75,-10.6; 23 2.25,-10.6; 24 2.75,-10.6; 25 3.25,-10.6; 26 3.75,-10.6; 27 4.25,-10.6; 28 4.75,-10.6; 29 5.25,-10.6; 30 5.75,-10.6; 31 6.25,-10.6; 32 6.75,-10.6; 33 7.25,-10.6; 34 7.75,-10.6; 35 8.25,-10.6; 36 8.75,-10.6; 73 8.75,10.6; 74 8.25,10.6; 75 7.75,10.6; 76 7.25,10.6; 77 6.75,10.6; 78 6.25,10.6; 79 5.75,10.6; 80 5.25,10.6; 81 4.75,10.6; 82 4.25,10.6; 83 3.75,10.6; 84 3.25,10.6; 85 2.75,10.6; 86 2.25,10.6; 87 1.75,10.6; 88 1.25,10.6; 89 0.75,10.6; 90 0.25,10.6; 91 -0.25,10.6; 92 -0.75,10.6; 93 -1.25,10.6; 94 -1.75,10.6; 95 -2.25,10.6; 96 -2.75,10.6; 97 -3.25,10.6; 98 -3.75,10.6; 99 -4.25,10.6; 100 -4.75,10.6; 101 -5.25,10.6; 102 -5.75,10.6; 103 -6.25,10.6; 104 -6.75,10.6; 105 -7.25,10.6; 106 -7.75,10.6; 107 -8.25,10.6; 108 -8.75,10.6
smd 1.6 x 0.3: 37 10.6,-8.75; 38 10.6,-8.25; 39 10.6,-7.75; 40 10.6,-7.25; 41 10.6,-6.75; 42 10.6,-6.25; 43 10.6,-5.75; 44 10.6,-5.25; 45 10.6,-4.75; 46 10.6,-4.25; 47 10.6,-3.75; 48 10.6,-3.25; 49 10.6,-2.75; 50 10.6,-2.25; 51 10.6,-1.75; 52 10.6,-1.25; 53 10.6,-0.75; 54 10.6,-0.25; 55 10.6,0.25; 56 10.6,0.75; 57 10.6,1.25; 58 10.6,1.75; 59 10.6,2.25; 60 10.6,2.75; 61 10.6,3.25; 62 10.6,3.75; 63 10.6,4.25; 64 10.6,4.75; 65 10.6,5.25; 66 10.6,5.75; 67 10.6,6.25; 68 10.6,6.75; 69 10.6,7.25; 70 10.6,7.75; 71 10.6,8.25; 72 10.6,8.75; 109 -10.6,8.75; 110 -10.6,8.25; 111 -10.6,7.75; 112 -10.6,7.25; 113 -10.6,6.75; 114 -10.6,6.25; 115 -10.6,5.75; 116 -10.6,5.25; 117 -10.6,4.75; 118 -10.6,4.25; 119 -10.6,3.75; 120 -10.6,3.25; 121 -10.6,2.75; 122 -10.6,2.25; 123 -10.6,1.75; 124 -10.6,1.25; 125 -10.6,0.75; 126 -10.6,0.25; 127 -10.6,-0.25; 128 -10.6,-0.75; 129 -10.6,-1.25; 130 -10.6,-1.75; 131 -10.6,-2.25; 132 -10.6,-2.75; 133 -10.6,-3.25; 134 -10.6,-3.75; 135 -10.6,-4.25; 136 -10.6,-4.75; 137 -10.6,-5.25; 138 -10.6,-5.75; 139 -10.6,-6.25; 140 -10.6,-6.75; 141 -10.6,-7.25; 142 -10.6,-7.75; 143 -10.6,-8.25; 144 -10.6,-8.75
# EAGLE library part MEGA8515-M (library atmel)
MICROCONTROLLER 8 Kbytes FLASH 512 bytes SRAM 512 bytes EEPROM USART 8-channel 10 bit ADC Source: avr.lbr

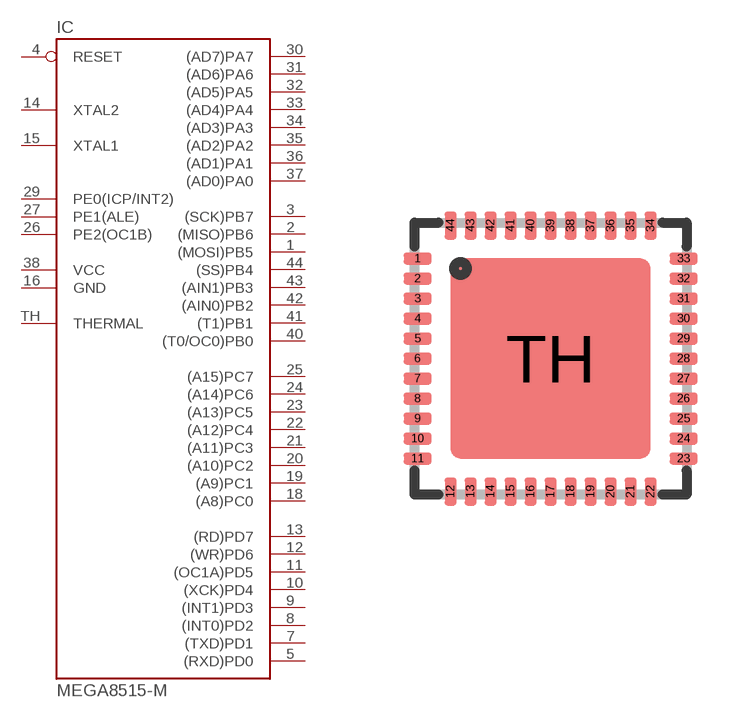
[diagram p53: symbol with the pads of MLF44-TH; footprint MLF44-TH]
Designator prefix IC

## MEGA8515-M-M (OC_FARNELL: unknown; OC_NEWARK: unknown)  [MLF44-TH]
1  (MOSI)PB5
2  (MISO)PB6
3  (SCK)PB7
4  RESET  in
5  (RXD)PD0
6  NC1  nc
7  (TXD)PD1
8  (INT0)PD2
9  (INT1)PD3
10  (XCK)PD4
11  (OC1A)PD5
12  (WR)PD6
13  (RD)PD7
14  XTAL2
15  XTAL1
16  GND  pwr
17  NC2  nc
18  (A8)PC0
19  (A9)PC1
20  (A10)PC2
21  (A11)PC3
22  (A12)PC4
23  (A13)PC5
24  (A14)PC6
25  (A15)PC7
26  PE2(OC1B)
27  PE1(ALE)
28  NC3  nc
29  PE0(ICP/INT2)
30  (AD7)PA7
31  (AD6)PA6
32  (AD5)PA5
33  (AD4)PA4
34  (AD3)PA3
35  (AD2)PA2
36  (AD1)PA1
37  (AD0)PA0
38  VCC  pwr
39  NC4  nc
40  (T0/OC0)PB0
41  (T1)PB1
42  (AIN0)PB2
43  (AIN1)PB3
44  (SS)PB4
TH  THERMAL  in

## Footprint MLF44-TH (pad centres in mm)
44M1 Micro Lead Frame package (MLF) Source: http://www.atmel.com/dyn/resources/prod_documents/doc2593.pdf
smd 0.7 x 0.3: 1 -3.325,2.5; 2 -3.325,2; 3 -3.325,1.5; 4 -3.325,1; 5 -3.325,0.5; 6 -3.325,0; 7 -3.325,-0.5; 8 -3.325,-1; 9 -3.325,-1.5; 10 -3.325,-2; 11 -3.325,-2.5; 23 3.325,-2.5; 24 3.325,-2; 25 3.325,-1.5; 26 3.325,-1; 27 3.325,-0.5; 28 3.325,0; 29 3.325,0.5; 30 3.325,1; 31 3.325,1.5; 32 3.325,2; 33 3.325,2.5
smd 0.3 x 0.7: 12 -2.5,-3.325; 13 -2,-3.325; 14 -1.5,-3.325; 15 -1,-3.325; 16 -0.5,-3.325; 17 0,-3.325; 18 0.5,-3.325; 19 1,-3.325; 20 1.5,-3.325; 21 2,-3.325; 22 2.5,-3.325; 34 2.5,3.325; 35 2,3.325; 36 1.5,3.325; 37 1,3.325; 38 0.5,3.325; 39 0,3.325; 40 -0.5,3.325; 41 -1,3.325; 42 -1.5,3.325; 43 -2,3.325; 44 -2.5,3.325
smd 5 x 5: TH 0,0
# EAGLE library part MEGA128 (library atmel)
MICROCONTROLLER 128 Kbytes FLASH 4 Kbytes SRAM 4 Kbytes EEPROM DUAL USART 8-channel 10 bit ADC Source: avr.lbr

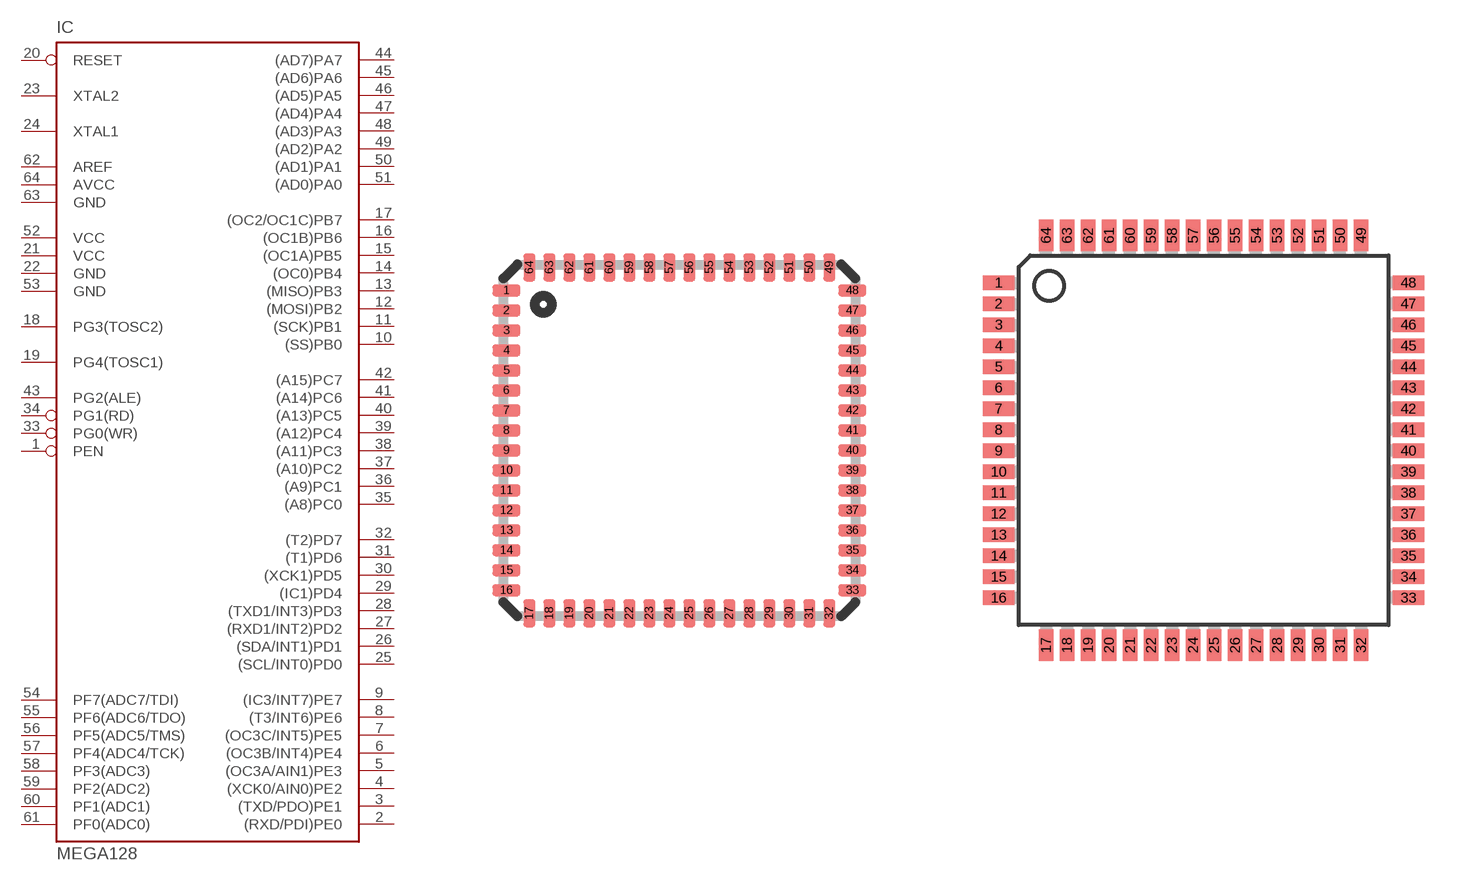
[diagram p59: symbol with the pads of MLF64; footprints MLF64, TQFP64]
Designator prefix IC

## MEGA128-M (MPN: ATMEGA128-16MU; OC_FARNELL: 1455093; OC_NEWARK: 58M3717)  [MLF64]
1  PEN  in
2  (RXD/PDI)PE0
3  (TXD/PDO)PE1
4  (XCK0/AIN0)PE2
5  (OC3A/AIN1)PE3
6  (OC3B/INT4)PE4
7  (OC3C/INT5)PE5
8  (T3/INT6)PE6
9  (IC3/INT7)PE7
10  (SS)PB0
11  (SCK)PB1
12  (MOSI)PB2
13  (MISO)PB3
14  (OC0)PB4
15  (OC1A)PB5
16  (OC1B)PB6
17  (OC2/OC1C)PB7
18  PG3(TOSC2)
19  PG4(TOSC1)
20  RESET  in
21  VCC  pwr
22  GND  pwr
23  XTAL2
24  XTAL1
25  (SCL/INT0)PD0
26  (SDA/INT1)PD1
27  (RXD1/INT2)PD2
28  (TXD1/INT3)PD3
29  (IC1)PD4
30  (XCK1)PD5
31  (T1)PD6
32  (T2)PD7
33  PG0(WR)
34  PG1(RD)
35  (A8)PC0  out
36  (A9)PC1  out
37  (A10)PC2  out
38  (A11)PC3  out
39  (A12)PC4  out
40  (A13)PC5  out
41  (A14)PC6  out
42  (A15)PC7  out
43  PG2(ALE)
44  (AD7)PA7
45  (AD6)PA6
46  (AD5)PA5
47  (AD4)PA4
48  (AD3)PA3
49  (AD2)PA2
50  (AD1)PA1
51  (AD0)PA0
52  VCC  pwr
53  GND  pwr
54  PF7(ADC7/TDI)  in
55  PF6(ADC6/TDO)  in
56  PF5(ADC5/TMS)  in
57  PF4(ADC4/TCK)  in
58  PF3(ADC3)  in
59  PF2(ADC2)  in
60  PF1(ADC1)  in
61  PF0(ADC0)  in
62  AREF  pas
63  GND  pwr
64  AVCC  pwr

## MEGA128-A (MPN: ATMEGA128-16AU; OC_FARNELL: 9171118; OC_NEWARK: 95K7364)  [TQFP64]
Pads as for MLF64

## Footprint MLF64 (pad centres in mm)
64M1 Micro Lead Frame package (MLF)
smd 0.7 x 0.3: 1 -4.325,3.75; 2 -4.325,3.25; 3 -4.325,2.75; 4 -4.325,2.25; 5 -4.325,1.75; 6 -4.325,1.25; 7 -4.325,0.75; 8 -4.325,0.25; 9 -4.325,-0.25; 10 -4.325,-0.75; 11 -4.325,-1.25; 12 -4.325,-1.75; 13 -4.325,-2.25; 14 -4.325,-2.75; 15 -4.325,-3.25; 16 -4.325,-3.75; 33 4.325,-3.75; 34 4.325,-3.25; 35 4.325,-2.75; 36 4.325,-2.25; 37 4.325,-1.75; 38 4.325,-1.25; 39 4.325,-0.75; 40 4.325,-0.25; 41 4.325,0.25; 42 4.325,0.75; 43 4.325,1.25; 44 4.325,1.75; 45 4.325,2.25; 46 4.325,2.75; 47 4.325,3.25; 48 4.325,3.75
smd 0.3 x 0.7: 17 -3.75,-4.325; 18 -3.25,-4.325; 19 -2.75,-4.325; 20 -2.25,-4.325; 21 -1.75,-4.325; 22 -1.25,-4.325; 23 -0.75,-4.325; 24 -0.25,-4.325; 25 0.25,-4.325; 26 0.75,-4.325; 27 1.25,-4.325; 28 1.75,-4.325; 29 2.25,-4.325; 30 2.75,-4.325; 31 3.25,-4.325; 32 3.75,-4.325; 49 3.75,4.325; 50 3.25,4.325; 51 2.75,4.325; 52 2.25,4.325; 53 1.75,4.325; 54 1.25,4.325; 55 0.75,4.325; 56 0.25,4.325; 57 -0.25,4.325; 58 -0.75,4.325; 59 -1.25,4.325; 60 -1.75,4.325; 61 -2.25,4.325; 62 -2.75,4.325; 63 -3.25,4.325; 64 -3.75,4.325

## Footprint TQFP64 (pad centres in mm)
Thin Plasic Quad Flat Package Updated from atml.lbr 17.01.2005 alf@cadsoft.de
smd 1.194 x 0.559: 1 -7.8,6; 2 -7.8,5.2; 3 -7.8,4.4; 4 -7.8,3.6; 5 -7.8,2.8; 6 -7.8,2; 7 -7.8,1.2; 8 -7.8,0.4; 9 -7.8,-0.4; 10 -7.8,-1.2; 11 -7.8,-2; 12 -7.8,-2.8; 13 -7.8,-3.6; 14 -7.8,-4.4; 15 -7.8,-5.2; 16 -7.8,-6; 33 7.8,-6; 34 7.8,-5.2; 35 7.8,-4.4; 36 7.8,-3.6; 37 7.8,-2.8; 38 7.8,-2; 39 7.8,-1.2; 40 7.8,-0.4; 41 7.8,0.4; 42 7.8,1.2; 43 7.8,2; 44 7.8,2.8; 45 7.8,3.6; 46 7.8,4.4; 47 7.8,5.2; 48 7.8,6
smd 0.559 x 1.194: 17 -6,-7.8; 18 -5.2,-7.8; 19 -4.4,-7.8; 20 -3.6,-7.8; 21 -2.8,-7.8; 22 -2,-7.8; 23 -1.2,-7.8; 24 -0.4,-7.8; 25 0.4,-7.8; 26 1.2,-7.8; 27 2,-7.8; 28 2.8,-7.8; 29 3.6,-7.8; 30 4.4,-7.8; 31 5.2,-7.8; 32 6,-7.8; 49 6,7.8; 50 5.2,7.8; 51 4.4,7.8; 52 3.6,7.8; 53 2.8,7.8; 54 2,7.8; 55 1.2,7.8; 56 0.4,7.8; 57 -0.4,7.8; 58 -1.2,7.8; 59 -2,7.8; 60 -2.8,7.8; 61 -3.6,7.8; 62 -4.4,7.8; 63 -5.2,7.8; 64 -6,7.8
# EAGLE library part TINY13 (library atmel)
8-bit AVR Microcontroller with 1K Bytes In-System Programmable Flash Source: http://www.atmel.com/dyn/resources/prod_documents/2535S.pdf

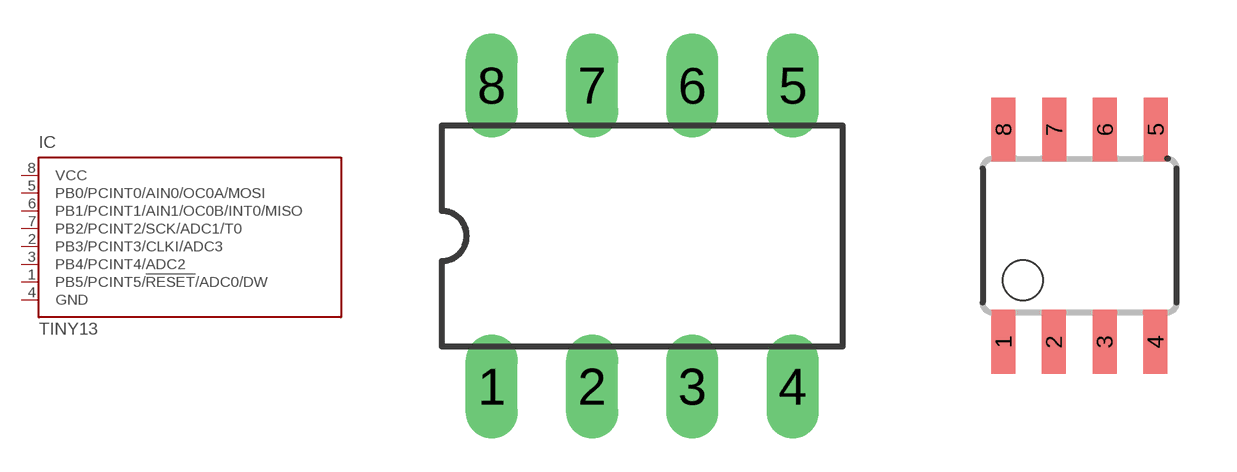
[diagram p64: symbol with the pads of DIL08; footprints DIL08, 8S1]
Designator prefix IC

## TINY13-20PU (MPN: ATTINY13-20PU; OC_FARNELL: 9171550; OC_NEWARK: 96K6521), TINY13V-10PU (MPN: ATTINY13V-10PU; OC_FARNELL: 9171576; OC_NEWARK: 96K6523)  [DIL08]
1  PB5/PCINT5/!RESET!/ADC0/DW
2  PB3/PCINT3/CLKI/ADC3
3  PB4/PCINT4/ADC2
4  GND  pwr
5  PB0/PCINT0/AIN0/OC0A/MOSI
6  PB1/PCINT1/AIN1/OC0B/INT0/MISO
7  PB2/PCINT2/SCK/ADC1/T0
8  VCC  pwr

## TINY13-20SSU (MPN: ATTINY13-20SSU; OC_FARNELL: 1455133; OC_NEWARK: 58M3771), TINY13V-10SSU (MPN: ATTINY13V-10SSU; OC_FARNELL: 1455135; OC_NEWARK: 58M3773)  [8S1]
Pads as for DIL08

## TINY13-20SU (MPN: ATTINY13-20SU; OC_FARNELL: 9171568; OC_NEWARK: 96K6522), TINY13V-10SU (MPN: ATTINY13V-10SU; OC_FARNELL: 9171584; OC_NEWARK: 96K6524)  [8S2]
Pads as for DIL08

## Footprint DIL08 (pad centres in mm)
Dual In Line
drill 0.813 long: 1 -3.81,-3.81; 2 -1.27,-3.81; 3 1.27,-3.81; 4 3.81,-3.81; 5 3.81,3.81; 6 1.27,3.81; 7 -1.27,3.81; 8 -3.81,3.81

## Footprint 8S1 (pad centres in mm)
8S1 8-lead (0.150" Wide Body) Plastic Gull Wing Small Outline (JEDEC SOIC) Source: http://www.atmel.com/dyn/resources/prod_documents/2535S.pdf
smd 0.6 x 1.6: 1 -1.905,-2.654; 2 -0.645,-2.654; 3 0.625,-2.654; 4 1.895,-2.654; 5 1.905,2.654; 6 0.635,2.654; 7 -0.635,2.654; 8 -1.905,2.654

## Footprint 8S2 (pad centres in mm)
8S2 8-lead, 0.208 Body Plastic Small Outline Package (EIAJ) Source: http://www.atmel.com/dyn/resources/prod_documents/2535S.pdf
smd 0.5 x 1.4: 1 -1.905,-3.404; 2 -0.645,-3.404; 3 0.625,-3.404; 4 1.895,-3.404; 5 1.905,3.404; 6 0.635,3.404; 7 -0.635,3.404; 8 -1.905,3.404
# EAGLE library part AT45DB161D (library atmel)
16-megabit 2.5V or 2.7V DataFlash Source: http://www.atmel.com/dyn/resources/prod_documents/doc3500.pdf

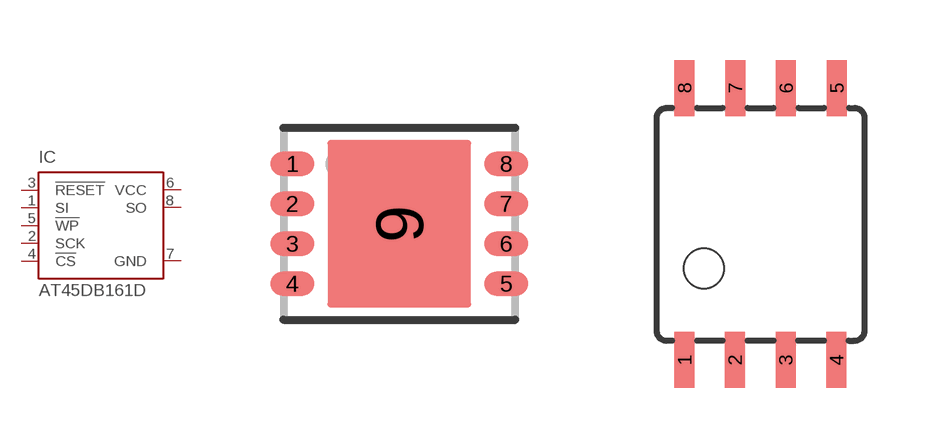
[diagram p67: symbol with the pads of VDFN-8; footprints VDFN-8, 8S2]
Designator prefix IC

## AT45DB161D-MU (MF: ATMEL; MPN: AT45DB161D-SU; OC_FARNELL: 1455040)  [VDFN-8]
1  SI  in
2  SCK  in
3  !RESET  in
4  !CS  in
5  !WP  in
6  VCC  pwr
7  GND  pwr
8  SO  out

## AT45DB161D-SU (MF: ATMEL; MPN: AT45DB161D-SU; OC_FARNELL: 1455040)  [8S2]
Pads as for VDFN-8

## Footprint VDFN-8 (pad centres in mm)
8M1-A-MLF (VDFN) 6 x 5 mm Source: http://www.atmel.com/dyn/resources/prod_documents/doc3500.pdf
smd 1.1 x 0.6: 1 -2.675,1.5; 2 -2.675,0.5; 3 -2.675,-0.5; 4 -2.675,-1.5; 5 2.675,-1.5; 6 2.675,-0.5; 7 2.675,0.5; 8 2.675,1.5
smd 3.6 x 4.2: 9 0,0

## Footprint 8S2 (pad centres in mm)
8S2 8-lead, 0.208 Body Plastic Small Outline Package (EIAJ) Source: http://www.atmel.com/dyn/resources/prod_documents/2535S.pdf
smd 0.5 x 1.4: 1 -1.905,-3.404; 2 -0.645,-3.404; 3 0.625,-3.404; 4 1.895,-3.404; 5 1.905,3.404; 6 0.635,3.404; 7 -0.635,3.404; 8 -1.905,3.404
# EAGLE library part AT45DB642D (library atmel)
Flash-Memory 64-Megabit 2 .7-volt, Dual-interface, DataFlash Source: http://www.atmel.com/dyn/resources/prod_documents/doc3542.pdf

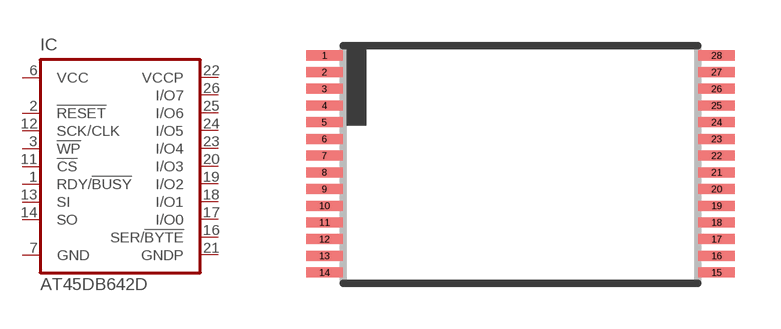
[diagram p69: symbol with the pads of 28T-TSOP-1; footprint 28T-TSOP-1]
Designator prefix IC

## AT45DB642D (MPN: AT45DB642D-TU; OC_FARNELL: 1095799; OC_NEWARK: 51P1801)  [28T-TSOP-1]
1  RDY/!BUSY  out
2  !RESET  in
3  !WP  in
6  VCC  pwr
7  GND  pwr
11  !CS  in
12  SCK/CLK  in
13  SI  in
14  SO  out
16  SER/!BYTE  in
17  I/O0
18  I/O1
19  I/O2
20  I/O3
21  GNDP  pwr
22  VCCP  pwr
23  I/O4
24  I/O5
25  I/O6
26  I/O7

## Footprint 28T-TSOP-1 (pad centres in mm)
28T 28-lead (8 x 13.4 mm) Plastic Thin Small Outline Type I (TSOP) Source: http://www.atmel.com/dyn/resources/prod_documents/doc3542.pdf
smd 1.2 x 0.33: 1 -6.45,3.575; 2 -6.45,3.025; 3 -6.45,2.475; 4 -6.45,1.925; 5 -6.45,1.375; 6 -6.45,0.825; 7 -6.45,0.275; 8 -6.45,-0.275; 9 -6.45,-0.825; 10 -6.45,-1.375; 11 -6.45,-1.925; 12 -6.45,-2.475; 13 -6.45,-3.025; 14 -6.45,-3.575; 15 6.45,-3.575; 16 6.45,-3.025; 17 6.45,-2.475; 18 6.45,-1.925; 19 6.45,-1.375; 20 6.45,-0.825; 21 6.45,-0.275; 22 6.45,0.275; 23 6.45,0.825; 24 6.45,1.375; 25 6.45,1.925; 26 6.45,2.475; 27 6.45,3.025; 28 6.45,3.575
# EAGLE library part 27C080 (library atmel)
8-Megabit (1Mx8) OTP EPROM

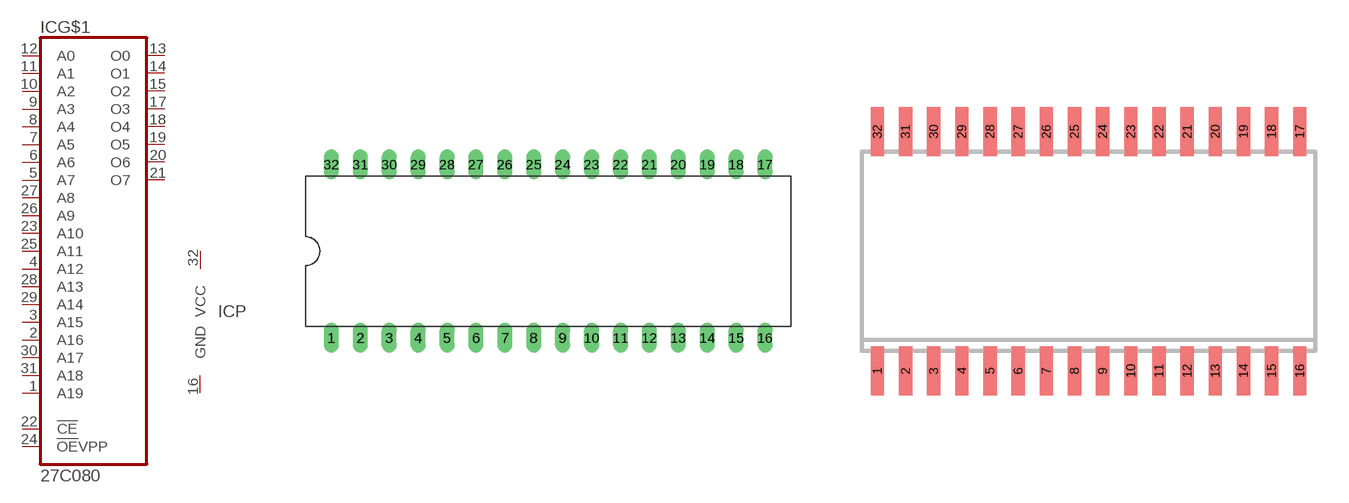
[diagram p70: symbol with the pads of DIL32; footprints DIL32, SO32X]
Designator prefix IC; gates G$1=27C080 P=VCCGND

## 27C08032P6 (MPN: AT27C080-90PU; OC_FARNELL: 1455026; OC_NEWARK: 58M3824)  [DIL32]
1  G$1:A19  in
2  G$1:A16  in
3  G$1:A15  in
4  G$1:A12  in
5  G$1:A7  in
6  G$1:A6  in
7  G$1:A5  in
8  G$1:A4  in
9  G$1:A3  in
10  G$1:A2  in
11  G$1:A1  in
12  G$1:A0  in
13  G$1:O0  hiz
14  G$1:O1  hiz
15  G$1:O2  hiz
16  P:GND  pwr
17  G$1:O3  hiz
18  G$1:O4  hiz
19  G$1:O5  hiz
20  G$1:O6  hiz
21  G$1:O7  hiz
22  G$1:!CE  in
23  G$1:A10  in
24  G$1:!OE!VPP  in
25  G$1:A11  in
26  G$1:A9  in
27  G$1:A8  in
28  G$1:A13  in
29  G$1:A14  in
30  G$1:A17  in
31  G$1:A18  in
32  P:VCC  pwr

## 27C080R (OC_FARNELL: unknown; OC_NEWARK: unknown)  [SO32X]
Pads as for DIL32

## 27C080J (MPN: AT27C080-90JU; OC_FARNELL: 1455025; OC_NEWARK: 58M3823)  [PLCC32R]
Pads as for DIL32

## 27C080T (OC_FARNELL: unknown; OC_NEWARK: unknown)  [TSOP32]
1  G$1:A11  in
2  G$1:A9  in
3  G$1:A8  in
4  G$1:A13  in
5  G$1:A14  in
6  G$1:A17  in
7  G$1:A18  in
8  P:VCC  pwr
9  G$1:A19  in
10  G$1:A16  in
11  G$1:A15  in
12  G$1:A12  in
13  G$1:A7  in
14  G$1:A6  in
15  G$1:A5  in
16  G$1:A4  in
17  G$1:A3  in
18  G$1:A2  in
19  G$1:A1  in
20  G$1:A0  in
21  G$1:O0  hiz
22  G$1:O1  hiz
23  G$1:O2  hiz
24  P:GND  pwr
25  G$1:O3  hiz
26  G$1:O4  hiz
27  G$1:O5  hiz
28  G$1:O6  hiz
29  G$1:O7  hiz
30  G$1:!CE  in
31  G$1:A10  in
32  G$1:!OE!VPP  in

## Footprint DIL32 (pad centres in mm)
Dual In Line
drill 0.813 long: 1 -19.05,-7.62; 2 -16.51,-7.62; 3 -13.97,-7.62; 4 -11.43,-7.62; 5 -8.89,-7.62; 6 -6.35,-7.62; 7 -3.81,-7.62; 8 -1.27,-7.62; 9 1.27,-7.62; 10 3.81,-7.62; 11 6.35,-7.62; 12 8.89,-7.62; 13 11.43,-7.62; 14 13.97,-7.62; 15 16.51,-7.62; 16 19.05,-7.62; 17 19.05,7.62; 18 16.51,7.62; 19 13.97,7.62; 20 11.43,7.62; 21 8.89,7.62; 22 6.35,7.62; 23 3.81,7.62; 24 1.27,7.62; 25 -1.27,7.62; 26 -3.81,7.62; 27 -6.35,7.62; 28 -8.89,7.62; 29 -11.43,7.62; 30 -13.97,7.62; 31 -16.51,7.62; 32 -19.05,7.62

## Footprint SO32X (pad centres in mm)
SMALL OUTLINE INTEGRATED CIRCUIT extra wide body 8.9 mm/JEDEC MO-120AC
smd 0.6 x 2.2: 1 -9.525,-5.4; 2 -8.255,-5.4; 3 -6.985,-5.4; 4 -5.715,-5.4; 5 -4.445,-5.4; 6 -3.175,-5.4; 7 -1.905,-5.4; 8 -0.635,-5.4; 9 0.635,-5.4; 10 1.905,-5.4; 11 3.175,-5.4; 12 4.445,-5.4; 13 5.715,-5.4; 14 6.985,-5.4; 15 8.255,-5.4; 16 9.525,-5.4; 17 9.525,5.4; 18 8.255,5.4; 19 6.985,5.4; 20 5.715,5.4; 21 4.445,5.4; 22 3.175,5.4; 23 1.905,5.4; 24 0.635,5.4; 25 -0.635,5.4; 26 -1.905,5.4; 27 -3.175,5.4; 28 -4.445,5.4; 29 -5.715,5.4; 30 -6.985,5.4; 31 -8.255,5.4; 32 -9.525,5.4

## Footprint PLCC32R (pad centres in mm)
PLASTIC LEADED CHIP CARRIER rectangle
smd 0.6 x 2.2: 1 0,6.9; 2 -1.27,6.9; 3 -2.54,6.9; 4 -3.81,6.9; 14 -3.81,-6.9; 15 -2.54,-6.9; 16 -1.27,-6.9; 17 0,-6.9; 18 1.27,-6.9; 19 2.54,-6.9; 20 3.81,-6.9; 30 3.81,6.9; 31 2.54,6.9; 32 1.27,6.9
smd 2.2 x 0.6: 5 -5.7,5.08; 6 -5.7,3.81; 7 -5.7,2.54; 8 -5.7,1.27; 9 -5.7,0; 10 -5.7,-1.27; 11 -5.7,-2.54; 12 -5.7,-3.81; 13 -5.7,-5.08; 21 5.7,-5.08; 22 5.7,-3.81; 23 5.7,-2.54; 24 5.7,-1.27; 25 5.7,0; 26 5.7,1.27; 27 5.7,2.54; 28 5.7,3.81; 29 5.7,5.08

## Footprint TSOP32 (pad centres in mm)
TSOP32 thin small outline package
smd 0.3 x 1.6: 1 -3.75,-9.6; 2 -3.25,-9.6; 3 -2.75,-9.6; 4 -2.25,-9.6; 5 -1.75,-9.6; 6 -1.25,-9.6; 7 -0.75,-9.6; 8 -0.25,-9.6; 9 0.25,-9.6; 10 0.75,-9.6; 11 1.25,-9.6; 12 1.75,-9.6; 13 2.25,-9.6; 14 2.75,-9.6; 15 3.25,-9.6; 16 3.75,-9.6; 17 3.75,9.59; 18 3.25,9.59; 19 2.75,9.59; 20 2.25,9.59; 21 1.75,9.59; 22 1.25,9.59; 23 0.75,9.59; 24 0.25,9.59; 25 -0.25,9.59; 26 -0.75,9.59; 27 -1.25,9.59; 28 -1.75,9.59; 29 -2.25,9.59; 30 -2.75,9.59; 31 -3.25,9.59; 32 -3.75,9.59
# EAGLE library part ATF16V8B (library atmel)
High perfomance CMOS (electrically erasable) programmable logic device (PLD) ABLE-Atmel-ABEL - P18V8R, P16V8C, P16V8AS, P17V8 COPL Atmel-WinCUPL - G16V8MS, G16V8MA, G16V8AS, G16V8 LOG/IC - GAL16V8_R, GAL16V8_G7, GAL16V8_C), GAL16V8 Tango-PLD - G16V8R, G16V8C, G16V8AS, G16V8 Source: http://www.atmel.com/dyn/resources/prod_documents/DOC0364.PDF

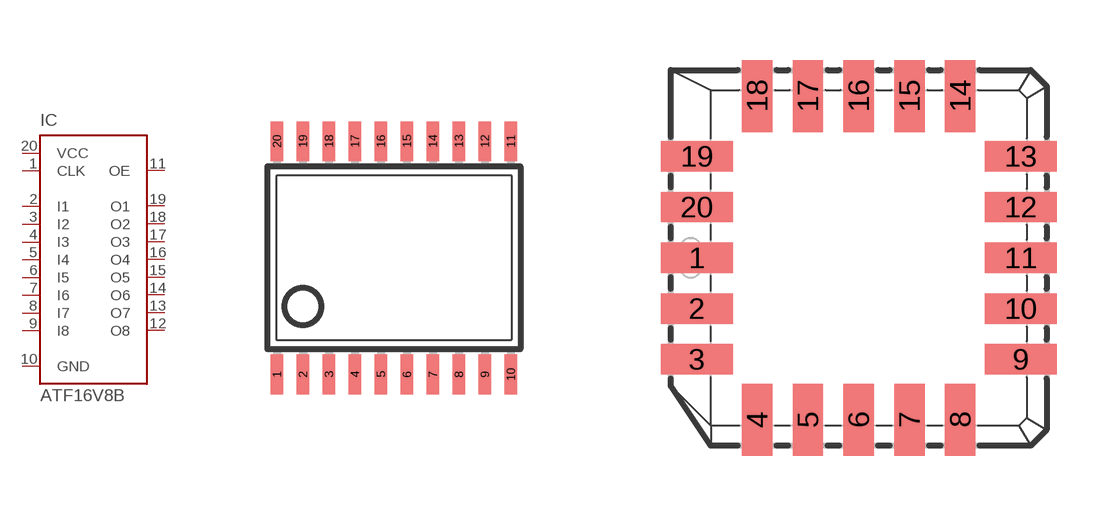
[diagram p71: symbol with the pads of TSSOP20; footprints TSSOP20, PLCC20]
Designator prefix IC

## ATF16V8BX (OC_FARNELL: unknown; OC_NEWARK: unknown)  [TSSOP20]
1  CLK  in
2  I1  in
3  I2  in
4  I3  in
5  I4  in
6  I5  in
7  I6  in
8  I7  in
9  I8  in
10  GND  pwr
11  OE  in
12  O8  out
13  O7  out
14  O6  out
15  O5  out
16  O4  out
17  O3  out
18  O2  out
19  O1  out
20  VCC  pwr

## ATF16V8BJ (MPN: ATF16V8CZ-15JU; OC_FARNELL: 1551767; OC_NEWARK: 94M6253)  [PLCC20]
Pads as for TSSOP20

## ATF16V8BP3 (MPN: ATF16V8CZ-15PU; OC_FARNELL: 1551768; OC_NEWARK: 94M6254)  [DIL20]
Pads as for TSSOP20

## ATF16V8BS (OC_FARNELL: unknown; OC_NEWARK: unknown)  [SO20L]
Pads as for TSSOP20

## Footprint TSSOP20 (pad centres in mm)
Thin Shrink Small Outline Plastic 20 MAX3223-MAX3243.pdf
smd 0.305 x 0.991: 1 -2.925,-2.918; 2 -2.275,-2.918; 3 -1.625,-2.918; 4 -0.975,-2.918; 5 -0.325,-2.918; 6 0.325,-2.918; 7 0.975,-2.918; 8 1.625,-2.918; 9 2.275,-2.918; 10 2.925,-2.918; 11 2.925,2.918; 12 2.275,2.918; 13 1.625,2.918; 14 0.975,2.918; 15 0.325,2.918; 16 -0.325,2.918; 17 -0.975,2.918; 18 -1.625,2.918; 19 -2.275,2.918; 20 -2.925,2.918

## Footprint PLCC20 (pad centres in mm)
Plastic Leaded Chip Carrier
smd 1.8 x 0.76: 1 -4.05,0; 2 -4.05,-1.27; 3 -4.05,-2.54; 9 4.05,-2.54; 10 4.05,-1.27; 11 4.05,0; 12 4.05,1.27; 13 4.05,2.54; 19 -4.05,2.54; 20 -4.05,1.27
smd 0.76 x 1.8: 4 -2.54,-4.05; 5 -1.27,-4.05; 6 0,-4.05; 7 1.27,-4.05; 8 2.54,-4.05; 14 2.54,4.05; 15 1.27,4.05; 16 0,4.05; 17 -1.27,4.05; 18 -2.54,4.05

## Footprint DIL20 (pad centres in mm)
Dual In Line
drill 0.813 long: 1 -11.43,-3.81; 2 -8.89,-3.81; 3 -6.35,-3.81; 4 -3.81,-3.81; 5 -1.27,-3.81; 6 1.27,-3.81; 7 3.81,-3.81; 8 6.35,-3.81; 9 8.89,-3.81; 10 11.43,-3.81; 11 11.43,3.81; 12 8.89,3.81; 13 6.35,3.81; 14 3.81,3.81; 15 1.27,3.81; 16 -1.27,3.81; 17 -3.81,3.81; 18 -6.35,3.81; 19 -8.89,3.81; 20 -11.43,3.81

## Footprint SO20L (pad centres in mm)
Small Outline Package SOIC 0.300"
smd 0.762 x 1.143: 1 -5.08,-5.131; 2 -3.81,-5.131; 3 -2.54,-5.131; 4 -1.27,-5.131; 5 0,-5.131; 6 1.27,-5.131; 7 2.54,-5.131; 8 3.81,-5.131; 9 5.08,-5.131; 10 6.35,-5.131; 11 6.35,4.369; 12 5.08,4.394; 13 3.81,4.394; 14 2.54,4.394; 15 1.27,4.394; 16 0,4.394; 17 -1.27,4.394; 18 -2.54,4.394; 19 -3.81,4.394; 20 -5.08,4.394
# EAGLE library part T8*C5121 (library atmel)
8-bit Microcontroller with Multiprotocol Smart Card Interface Source: Uploaded by Heiko Künzel from ATG Automatisierungstechnik Gera Mon Mar 10 13:32:48 2003 Atmel-Library mit zusätzlich T83C5121-Prozessor im SSOP24-Package.

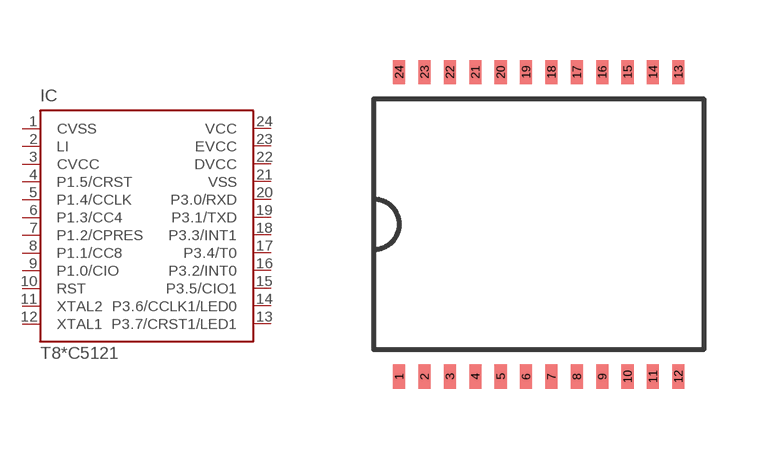
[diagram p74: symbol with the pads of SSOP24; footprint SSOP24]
Designator prefix IC

## T8C5121 (OC_FARNELL: unknown; OC_NEWARK: unknown)  [SSOP24]
1  CVSS  pwr
2  LI  pwr
3  CVCC  pwr
4  P1.5/CRST
5  P1.4/CCLK
6  P1.3/CC4
7  P1.2/CPRES
8  P1.1/CC8
9  P1.0/CIO
10  RST
11  XTAL2  in
12  XTAL1  out
13  P3.7/CRST1/LED1
14  P3.6/CCLK1/LED0
15  P3.5/CIO1
16  P3.2/INT0
17  P3.4/T0
18  P3.3/INT1
19  P3.1/TXD
20  P3.0/RXD
21  VSS  pwr
22  DVCC  pwr
23  EVCC  pas
24  VCC  pwr

## Footprint SSOP24 (pad centres in mm)
SSOP 24 Source: Uploaded by Heiko Künzel from ATG Automatisierungstechnik Gera Mon Mar 10 13:32:48 2003 Atmel-Library mit zusätzlich T83C5121-Prozessor im SSOP24-Package. Package centre and <NAME &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
smd 0.305 x 0.61: 1 -3.493,-3.81; 2 -2.857,-3.81; 3 -2.223,-3.81; 4 -1.587,-3.81; 5 -0.953,-3.81; 6 -0.318,-3.81; 7 0.318,-3.81; 8 0.953,-3.81; 9 1.587,-3.81; 10 2.223,-3.81; 11 2.857,-3.81; 12 3.493,-3.81; 13 3.493,3.81; 14 2.857,3.81; 15 2.223,3.81; 16 1.587,3.81; 17 0.953,3.81; 18 0.318,3.81; 19 -0.318,3.81; 20 -0.953,3.81; 21 -1.587,3.81; 22 -2.223,3.81; 23 -2.857,3.81; 24 -3.493,3.81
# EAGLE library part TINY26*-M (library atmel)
8-bit AVR Microcontroller with 2K Bytes Flash Source: http://www.atmel.com .. doc1477.pdf

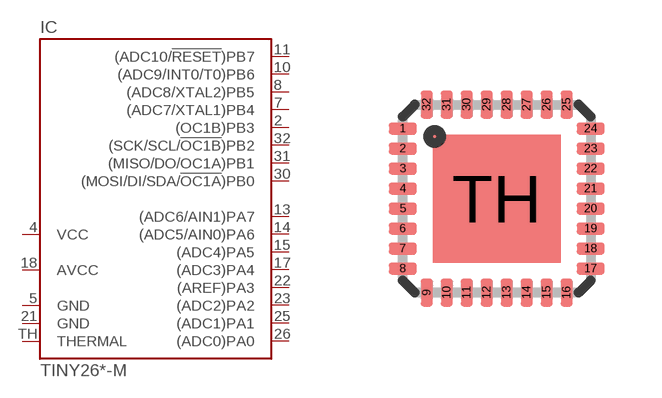
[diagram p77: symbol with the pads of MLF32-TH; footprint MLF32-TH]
Designator prefix IC

## TINY26-M (OC_FARNELL: unknown; OC_NEWARK: unknown), TINY26L-M (OC_FARNELL: unknown; OC_NEWARK: unknown)  [MLF32-TH]
2  (OC1B)PB3
4  VCC  pwr
5  GND  pwr
7  (ADC7/XTAL1)PB4
8  (ADC8/XTAL2)PB5
10  (ADC9/INT0/T0)PB6
11  (ADC10/!RESET!)PB7
13  (ADC6/AIN1)PA7
14  (ADC5/AIN0)PA6
15  (ADC4)PA5
17  (ADC3)PA4
18  AVCC  pwr
21  GND  pwr
22  (AREF)PA3
23  (ADC2)PA2
25  (ADC1)PA1
26  (ADC0)PA0
30  (MOSI/DI/SDA/!OC1A!)PB0
31  (MISO/DO/OC1A)PB1
32  (SCK/SCL/!OC1B!)PB2
TH  THERMAL  in

## Footprint MLF32-TH (pad centres in mm)
32M1-A Micro Lead Frame package (MLF)
smd 0.7 x 0.3: 1 -2.35,1.75; 2 -2.35,1.25; 3 -2.35,0.75; 4 -2.35,0.25; 5 -2.35,-0.25; 6 -2.35,-0.75; 7 -2.35,-1.25; 8 -2.35,-1.75; 17 2.35,-1.75; 18 2.35,-1.25; 19 2.35,-0.75; 20 2.35,-0.25; 21 2.35,0.25; 22 2.35,0.75; 23 2.35,1.25; 24 2.35,1.75
smd 0.3 x 0.7: 9 -1.75,-2.35; 10 -1.25,-2.35; 11 -0.75,-2.35; 12 -0.25,-2.35; 13 0.25,-2.35; 14 0.75,-2.35; 15 1.25,-2.35; 16 1.75,-2.35; 25 1.75,2.35; 26 1.25,2.35; 27 0.75,2.35; 28 0.25,2.35; 29 -0.25,2.35; 30 -0.75,2.35; 31 -1.25,2.35; 32 -1.75,2.35
smd 3.2 x 3.2: TH 0,0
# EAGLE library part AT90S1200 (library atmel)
MICROCONTROLLER 1 Kbytes FLASH 64 bytes EEPROM

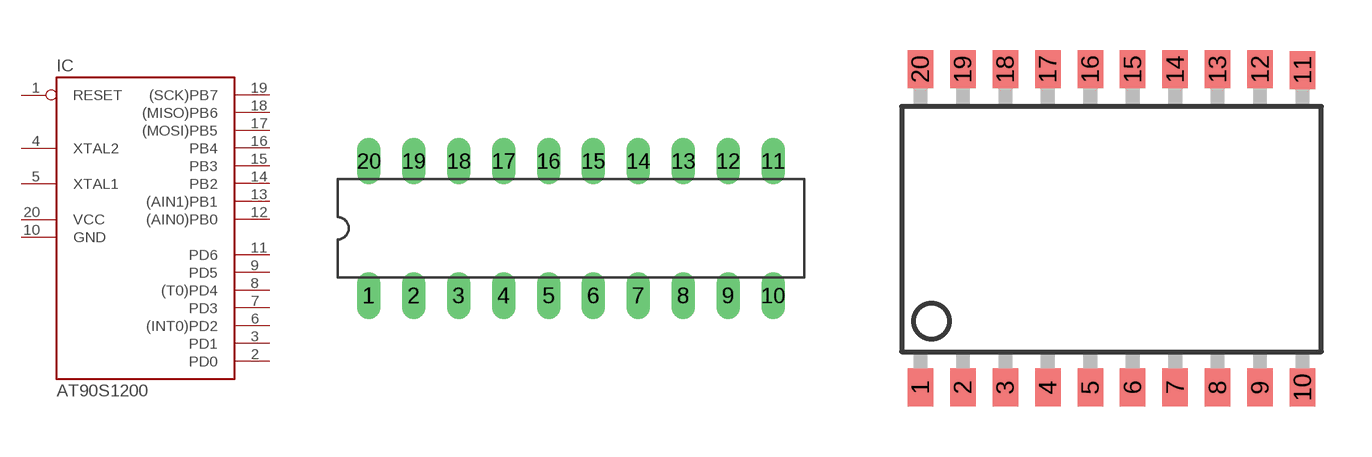
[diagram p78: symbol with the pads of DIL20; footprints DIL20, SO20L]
Designator prefix IC

## AT90S1200P (OC_FARNELL: unknown; OC_NEWARK: unknown)  [DIL20]
1  RESET
2  PD0
3  PD1
4  XTAL2
5  XTAL1
6  (INT0)PD2
7  PD3
8  (T0)PD4
9  PD5
10  GND  pwr
11  PD6
12  (AIN0)PB0
13  (AIN1)PB1
14  PB2
15  PB3
16  PB4
17  (MOSI)PB5
18  (MISO)PB6
19  (SCK)PB7
20  VCC  pwr

## AT90S1200S (OC_FARNELL: unknown; OC_NEWARK: unknown)  [SO20L]
Pads as for DIL20

## AT90S1200Y (OC_FARNELL: unknown; OC_NEWARK: unknown)  [SSOP20D8]
Pads as for DIL20

## Footprint DIL20 (pad centres in mm)
Dual In Line
drill 0.813 long: 1 -11.43,-3.81; 2 -8.89,-3.81; 3 -6.35,-3.81; 4 -3.81,-3.81; 5 -1.27,-3.81; 6 1.27,-3.81; 7 3.81,-3.81; 8 6.35,-3.81; 9 8.89,-3.81; 10 11.43,-3.81; 11 11.43,3.81; 12 8.89,3.81; 13 6.35,3.81; 14 3.81,3.81; 15 1.27,3.81; 16 -1.27,3.81; 17 -3.81,3.81; 18 -6.35,3.81; 19 -8.89,3.81; 20 -11.43,3.81

## Footprint SO20L (pad centres in mm)
Small Outline Package SOIC 0.300"
smd 0.762 x 1.143: 1 -5.08,-5.131; 2 -3.81,-5.131; 3 -2.54,-5.131; 4 -1.27,-5.131; 5 0,-5.131; 6 1.27,-5.131; 7 2.54,-5.131; 8 3.81,-5.131; 9 5.08,-5.131; 10 6.35,-5.131; 11 6.35,4.369; 12 5.08,4.394; 13 3.81,4.394; 14 2.54,4.394; 15 1.27,4.394; 16 0,4.394; 17 -1.27,4.394; 18 -2.54,4.394; 19 -3.81,4.394; 20 -5.08,4.394

## Footprint SSOP20D8 (pad centres in mm)
Plastic Shrink Small Outline Package
smd 0.305 x 1.245: 1 -2.794,-3.353; 2 -2.159,-3.353; 3 -1.524,-3.353; 4 -0.889,-3.353; 5 -0.254,-3.353; 6 0.381,-3.353; 7 1.016,-3.353; 8 1.651,-3.353; 9 2.286,-3.353; 10 2.921,-3.353; 11 2.921,3.251; 12 2.286,3.251; 13 1.651,3.251; 14 1.016,3.251; 15 0.381,3.251; 16 -0.254,3.251; 17 -0.889,3.251; 18 -1.524,3.251; 19 -2.159,3.251; 20 -2.794,3.251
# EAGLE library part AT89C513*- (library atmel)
8-bit Flash Microcontroller with Full Speed USB Device Source: http://www.atmel.com/dyn/resources/prod_documents/doc4136.pdf Data sheet mistake: define Packge type pin description for MLF48 but Order Number for QFN32 !?

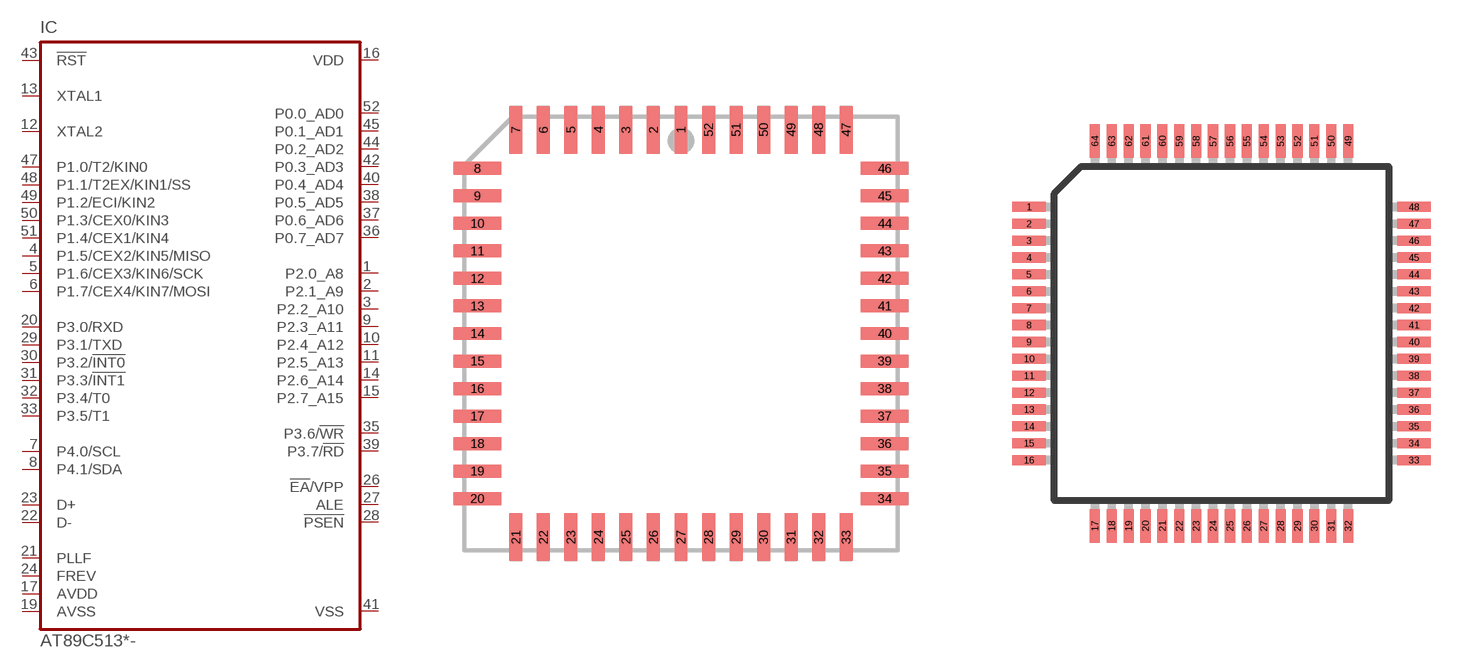
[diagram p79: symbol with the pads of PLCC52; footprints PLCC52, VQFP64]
Designator prefix IC

## AT89C5130-S (OC_FARNELL: unknown; OC_NEWARK: unknown), AT89C5131-S (MPN: AT89C5131A-S3SUM; OC_FARNELL: 1095721; OC_NEWARK: 96K6570)  [PLCC52]
1  P2.0_A8
2  P2.1_A9
3  P2.2_A10
4  P1.5/CEX2/KIN5/MISO
5  P1.6/CEX3/KIN6/SCK
6  P1.7/CEX4/KIN7/MOSI
7  P4.0/SCL
8  P4.1/SDA
9  P2.3_A11
10  P2.4_A12
11  P2.5_A13
12  XTAL2  in
13  XTAL1  in
14  P2.6_A14
15  P2.7_A15
16  VDD  pwr
17  AVDD  pwr
19  AVSS  pwr
20  P3.0/RXD
21  PLLF
22  D-
23  D+
24  FREV
26  !EA!/VPP  in
27  ALE
28  !PSEN  out
29  P3.1/TXD
30  P3.2/!INT0
31  P3.3/!INT1
32  P3.4/T0
33  P3.5/T1
35  P3.6/!WR
36  P0.7_AD7
37  P0.6_AD6
38  P0.5_AD5
39  P3.7/!RD
40  P0.4_AD4
41  VSS  pwr
42  P0.3_AD3
43  !RST  in
44  P0.2_AD2
45  P0.1_AD1
47  P1.0/T2/KIN0
48  P1.1/T2EX/KIN1/SS
49  P1.2/ECI/KIN2
50  P1.3/CEX0/KIN3
51  P1.4/CEX1/KIN4
52  P0.0_AD0

## AT89C5130-R (OC_FARNELL: unknown; OC_NEWARK: unknown), AT89C5131-R (OC_FARNELL: unknown; OC_NEWARK: unknown)  [VQFP64]
2  P2.3_A11
3  P2.4_A12
4  P2.5_A13
5  XTAL2  in
6  XTAL1  in
7  P2.6_A14
8  P2.7_A15
9  VDD  pwr
10  AVDD  pwr
12  AVSS  pwr
14  P3.0/RXD
19  PLLF
20  D-
21  D+
22  FREV
24  !EA!/VPP  in
25  ALE
26  !PSEN  out
27  P3.1/TXD
28  P3.2/!INT0
29  P3.3/!INT1
30  P3.4/T0
31  P3.5/T1
35  P3.6/!WR
36  P0.7_AD7
37  P0.6_AD6
38  P0.5_AD5
39  P3.7/!RD
40  P0.4_AD4
42  VSS  pwr
43  P0.3_AD3
44  !RST  in
45  P0.2_AD2
46  P0.1_AD1
50  P1.0/T2/KIN0
51  P1.1/T2EX/KIN1/SS
52  P1.2/ECI/KIN2
53  P1.3/CEX0/KIN3
54  P1.4/CEX1/KIN4
55  P0.0_AD0
56  P2.0_A8
57  P2.1_A9
58  P2.2_A10
59  P1.5/CEX2/KIN5/MISO
60  P1.6/CEX3/KIN6/SCK
61  P1.7/CEX4/KIN7/MOSI
62  P4.0/SCL
63  P4.1/SDA

## Footprint PLCC52 (pad centres in mm)
PLASTIC LEADED CHIP CARRIER square
smd 0.6 x 2.2: 1 0,9.4; 2 -1.27,9.4; 3 -2.54,9.4; 4 -3.81,9.4; 5 -5.08,9.4; 6 -6.35,9.4; 7 -7.62,9.4; 21 -7.62,-9.4; 22 -6.35,-9.4; 23 -5.08,-9.4; 24 -3.81,-9.4; 25 -2.54,-9.4; 26 -1.27,-9.4; 27 0,-9.4; 28 1.27,-9.4; 29 2.54,-9.4; 30 3.81,-9.4; 31 5.08,-9.4; 32 6.35,-9.4; 33 7.62,-9.4; 47 7.62,9.4; 48 6.35,9.4; 49 5.08,9.4; 50 3.81,9.4; 51 2.54,9.4; 52 1.27,9.4
smd 2.2 x 0.6: 8 -9.4,7.62; 9 -9.4,6.35; 10 -9.4,5.08; 11 -9.4,3.81; 12 -9.4,2.54; 13 -9.4,1.27; 14 -9.4,0; 15 -9.4,-1.27; 16 -9.4,-2.54; 17 -9.4,-3.81; 18 -9.4,-5.08; 19 -9.4,-6.35; 20 -9.4,-7.62; 34 9.4,-7.62; 35 9.4,-6.35; 36 9.4,-5.08; 37 9.4,-3.81; 38 9.4,-2.54; 39 9.4,-1.27; 40 9.4,0; 41 9.4,1.27; 42 9.4,2.54; 43 9.4,3.81; 44 9.4,5.08; 45 9.4,6.35; 46 9.4,7.62

## Footprint VQFP64 (pad centres in mm)
64-lead VQVP Source. http://www.atmel.com/dyn/resources/prod_documents/doc4136.pdf
smd 1 x 0.3: 1 -5.7,3.75; 2 -5.7,3.25; 3 -5.7,2.75; 4 -5.7,2.25; 5 -5.7,1.75; 6 -5.7,1.25; 7 -5.7,0.75; 8 -5.7,0.25; 9 -5.7,-0.25; 10 -5.7,-0.75; 11 -5.7,-1.25; 12 -5.7,-1.75; 13 -5.7,-2.25; 14 -5.7,-2.75; 15 -5.7,-3.25; 16 -5.7,-3.75; 33 5.7,-3.75; 34 5.7,-3.25; 35 5.7,-2.75; 36 5.7,-2.25; 37 5.7,-1.75; 38 5.7,-1.25; 39 5.7,-0.75; 40 5.7,-0.25; 41 5.7,0.25; 42 5.7,0.75; 43 5.7,1.25; 44 5.7,1.75; 45 5.7,2.25; 46 5.7,2.75; 47 5.7,3.25; 48 5.7,3.75
smd 0.3 x 1: 17 -3.75,-5.7; 18 -3.25,-5.7; 19 -2.75,-5.7; 20 -2.25,-5.7; 21 -1.75,-5.7; 22 -1.25,-5.7; 23 -0.75,-5.7; 24 -0.25,-5.7; 25 0.25,-5.7; 26 0.75,-5.7; 27 1.25,-5.7; 28 1.75,-5.7; 29 2.25,-5.7; 30 2.75,-5.7; 31 3.25,-5.7; 32 3.75,-5.7; 49 3.75,5.7; 50 3.25,5.7; 51 2.75,5.7; 52 2.25,5.7; 53 1.75,5.7; 54 1.25,5.7; 55 0.75,5.7; 56 0.25,5.7; 57 -0.25,5.7; 58 -0.75,5.7; 59 -1.25,5.7; 60 -1.75,5.7; 61 -2.25,5.7; 62 -2.75,5.7; 63 -3.25,5.7; 64 -3.75,5.7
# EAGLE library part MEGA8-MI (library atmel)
MICROCONTROLLER 8 Kbytes FLASH, 1 kbytes SRAM, 512 bytes EEPROM, USART, 6-channel 10 bit ADC, 2-channel 8 bit ADC Pin compatible with Atmega48, ATMega88, ATMega168 Source: avr.lbr

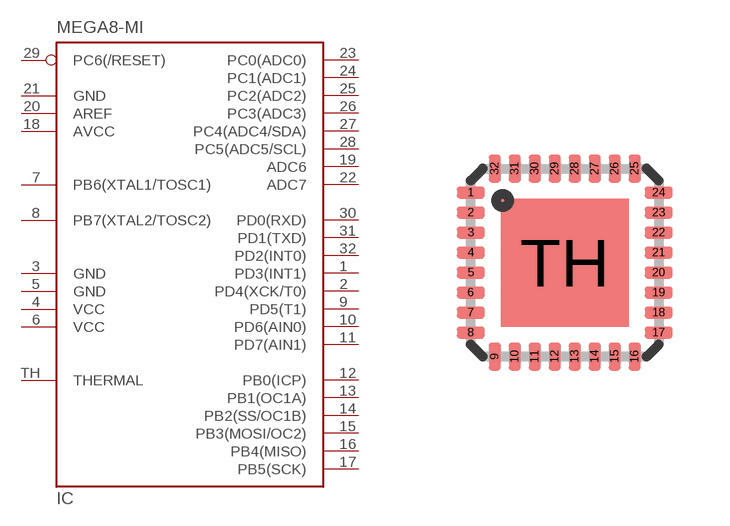
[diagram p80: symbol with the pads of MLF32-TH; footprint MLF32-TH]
Designator prefix IC

## MEGA8-MI (MPN: ATMEGA88PA-MU; OC_FARNELL: 1715491; OC_NEWARK: 15R0272)  [MLF32-TH]
1  PD3(INT1)
2  PD4(XCK/T0)
3  GND  pwr
4  VCC  pwr
5  GND  pwr
6  VCC  pwr
7  PB6(XTAL1/TOSC1)
8  PB7(XTAL2/TOSC2)
9  PD5(T1)
10  PD6(AIN0)
11  PD7(AIN1)
12  PB0(ICP)
13  PB1(OC1A)
14  PB2(SS/OC1B)
15  PB3(MOSI/OC2)
16  PB4(MISO)
17  PB5(SCK)
18  AVCC  pwr
19  ADC6
20  AREF  pas
21  GND  pwr
22  ADC7
23  PC0(ADC0)
24  PC1(ADC1)
25  PC2(ADC2)
26  PC3(ADC3)
27  PC4(ADC4/SDA)
28  PC5(ADC5/SCL)
29  PC6(/RESET)
30  PD0(RXD)
31  PD1(TXD)
32  PD2(INT0)
TH  THERMAL  pas

## Footprint MLF32-TH (pad centres in mm)
32M1-A Micro Lead Frame package (MLF)
smd 0.7 x 0.3: 1 -2.35,1.75; 2 -2.35,1.25; 3 -2.35,0.75; 4 -2.35,0.25; 5 -2.35,-0.25; 6 -2.35,-0.75; 7 -2.35,-1.25; 8 -2.35,-1.75; 17 2.35,-1.75; 18 2.35,-1.25; 19 2.35,-0.75; 20 2.35,-0.25; 21 2.35,0.25; 22 2.35,0.75; 23 2.35,1.25; 24 2.35,1.75
smd 0.3 x 0.7: 9 -1.75,-2.35; 10 -1.25,-2.35; 11 -0.75,-2.35; 12 -0.25,-2.35; 13 0.25,-2.35; 14 0.75,-2.35; 15 1.25,-2.35; 16 1.75,-2.35; 25 1.75,2.35; 26 1.25,2.35; 27 0.75,2.35; 28 0.25,2.35; 29 -0.25,2.35; 30 -0.75,2.35; 31 -1.25,2.35; 32 -1.75,2.35
smd 3.2 x 3.2: TH 0,0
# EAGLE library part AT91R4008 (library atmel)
AT91 ARM® Thumb® RISC-Controller Microcontroller AT91R40008

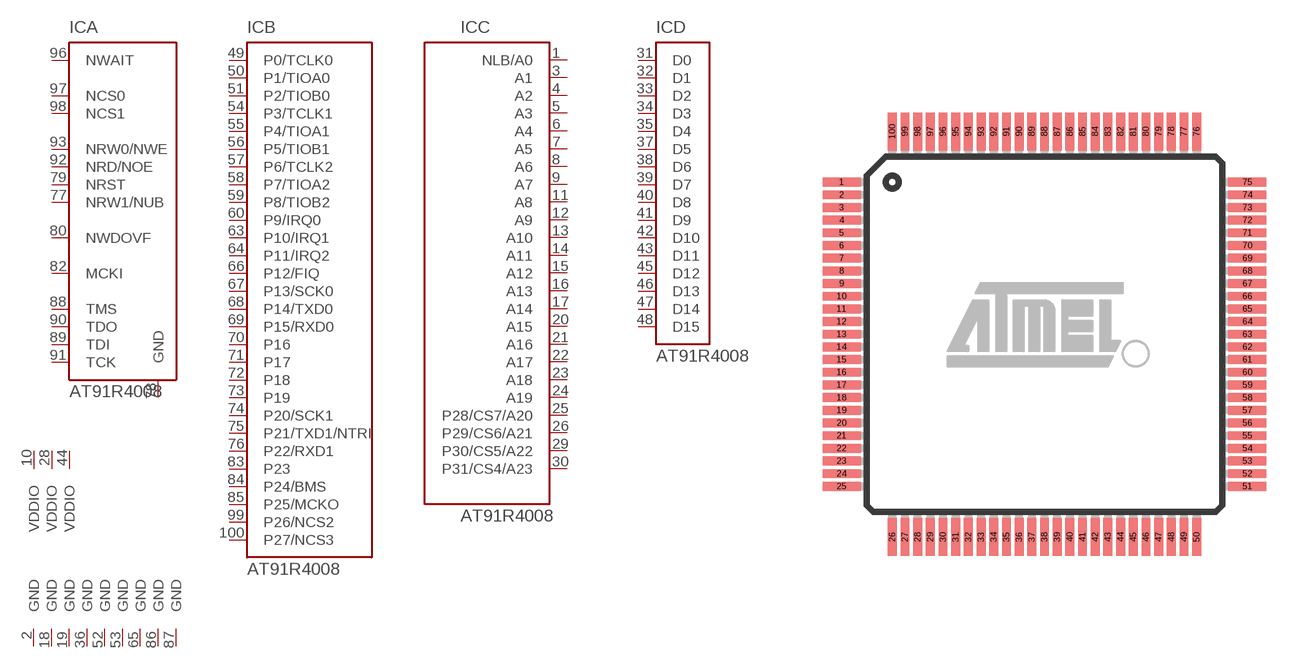
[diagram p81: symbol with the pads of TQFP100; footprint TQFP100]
Designator prefix IC; gates A=AT91R4008 B=AT91R4008-PARPORT C=AT91R4008-ADR D=D0-15 P1=GND P2=GND P3=GND P4=GND P5=GND P15=VDDIO P16=VDDIO P17=VDDIO P6=GND P7=GND P8=GND P9=GND P10=VDDIO P11=VDDIO P12=VDDCORE P13=VDDCORE P14=VDDCORE P18=VDDIO

## AT91R4008 (OC_FARNELL: unknown; OC_NEWARK: unknown)  [TQFP100]
1  C:NLB/A0  out
2  P1:GND  pwr
3  C:A1  out
4  C:A2  out
5  C:A3  out
6  C:A4  out
7  C:A5  out
8  C:A6  out
9  C:A7  out
10  P15:VDDIO  pwr
11  C:A8  out
12  C:A9  out
13  C:A10  out
14  C:A11  out
15  C:A12  out
16  C:A13  out
17  C:A14  out
18  P2:GND  pwr
19  P3:GND  pwr
20  C:A15  out
21  C:A16  out
22  C:A17  out
23  C:A18  out
24  C:A19  out
25  C:P28/CS7/A20  out
26  C:P29/CS6/A21  out
27  P12:VDDCORE  pwr
28  P16:VDDIO  pwr
29  C:P30/CS5/A22  out
30  C:P31/CS4/A23  out
31  D:D0  hiz
32  D:D1  hiz
33  D:D2  hiz
34  D:D3  hiz
35  D:D4  hiz
36  P4:GND  pwr
37  D:D5  hiz
38  D:D6  hiz
39  D:D7  hiz
40  D:D8  hiz
41  D:D9  hiz
42  D:D10  hiz
43  D:D11  hiz
44  P17:VDDIO  pwr
45  D:D12  hiz
46  D:D13  hiz
47  D:D14  hiz
48  D:D15  hiz
49  B:P0/TCLK0
50  B:P1/TIOA0
51  B:P2/TIOB0
52  P5:GND  pwr
53  P6:GND  pwr
54  B:P3/TCLK1
55  B:P4/TIOA1
56  B:P5/TIOB1
57  B:P6/TCLK2
58  B:P7/TIOA2
59  B:P8/TIOB2
60  B:P9/IRQ0
61  P13:VDDCORE  pwr
62  P10:VDDIO  pwr
63  B:P10/IRQ1
64  B:P11/IRQ2
65  P7:GND  pwr
66  B:P12/FIQ
67  B:P13/SCK0
68  B:P14/TXD0
69  B:P15/RXD0
70  B:P16
71  B:P17
72  B:P18
73  B:P19
74  B:P20/SCK1
75  B:P21/TXD1/NTRI
76  B:P22/RXD1
77  A:NRW1/NUB  out
78  A:GND  pwr
79  A:NRST  out
80  A:NWDOVF  out
81  P11:VDDIO  pwr
82  A:MCKI  in
83  B:P23
84  B:P24/BMS
85  B:P25/MCKO
86  P8:GND  pwr
87  P9:GND  pwr
88  A:TMS  in
89  A:TDI  in
90  A:TDO  out
91  A:TCK  in
92  A:NRD/NOE  out
93  A:NRW0/NWE  out
94  P14:VDDCORE  pwr
95  P18:VDDIO  pwr
96  A:NWAIT  in
97  A:NCS0  out
98  A:NCS1  out
99  B:P26/NCS2
100  B:P27/NCS3

## Footprint TQFP100 (pad centres in mm)
100-lead Thin Quad Flat Pack Package
smd 1.5 x 0.35: 1 -8,6; 2 -8,5.5; 3 -8,5; 4 -8,4.5; 5 -8,4; 6 -8,3.5; 7 -8,3; 8 -8,2.5; 9 -8,2; 10 -8,1.5; 11 -8,1; 12 -8,0.5; 13 -8,0; 14 -8,-0.5; 15 -8,-1; 16 -8,-1.5; 17 -8,-2; 18 -8,-2.5; 19 -8,-3; 20 -8,-3.5; 21 -8,-4; 22 -8,-4.5; 23 -8,-5; 24 -8,-5.5; 25 -8,-6; 51 8,-6; 52 8,-5.5; 53 8,-5; 54 8,-4.5; 55 8,-4; 56 8,-3.5; 57 8,-3; 58 8,-2.5; 59 8,-2; 60 8,-1.5; 61 8,-1; 62 8,-0.5; 63 8,0; 64 8,0.5; 65 8,1; 66 8,1.5; 67 8,2; 68 8,2.5; 69 8,3; 70 8,3.5; 71 8,4; 72 8,4.5; 73 8,5; 74 8,5.5; 75 8,6
smd 0.35 x 1.5: 26 -6,-8; 27 -5.5,-8; 28 -5,-8; 29 -4.5,-8; 30 -4,-8; 31 -3.5,-8; 32 -3,-8; 33 -2.5,-8; 34 -2,-8; 35 -1.5,-8; 36 -1,-8; 37 -0.5,-8; 38 0,-8; 39 0.5,-8; 40 1,-8; 41 1.5,-8; 42 2,-8; 43 2.5,-8; 44 3,-8; 45 3.5,-8; 46 4,-8; 47 4.5,-8; 48 5,-8; 49 5.5,-8; 50 6,-8; 76 6,8; 77 5.5,8; 78 5,8; 79 4.5,8; 80 4,8; 81 3.5,8; 82 3,8; 83 2.5,8; 84 2,8; 85 1.5,8; 86 1,8; 87 0.5,8; 88 0,8; 89 -0.5,8; 90 -1,8; 91 -1.5,8; 92 -2,8; 93 -2.5,8; 94 -3,8; 95 -3.5,8; 96 -4,8; 97 -4.5,8; 98 -5,8; 99 -5.5,8; 100 -6,8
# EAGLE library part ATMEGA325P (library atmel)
8-bit Microcontroller with 32K Bytes In-System Programmable Flash Source: http://www.atmel.com .. doc8023.pdf

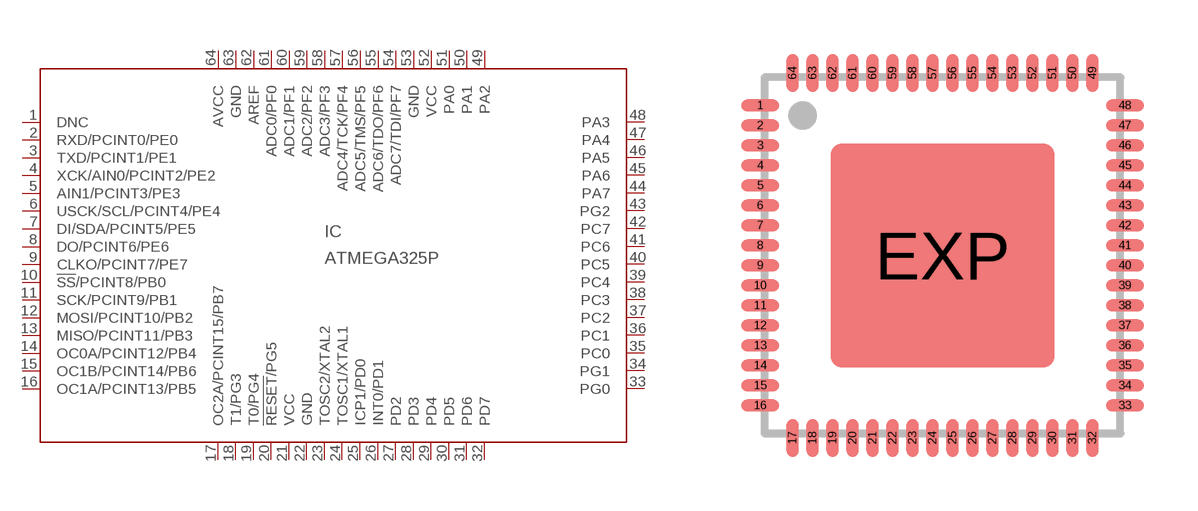
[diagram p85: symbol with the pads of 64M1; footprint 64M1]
Designator prefix IC

## ATMEGA325P (MPN: ATMEGA325PV-10AU; OC_FARNELL: 1636939; OC_NEWARK: 03P2025)  [64M1]
1  DNC  in
2  RXD/PCINT0/PE0
3  TXD/PCINT1/PE1
4  XCK/AIN0/PCINT2/PE2
5  AIN1/PCINT3/PE3
6  USCK/SCL/PCINT4/PE4
7  DI/SDA/PCINT5/PE5
8  DO/PCINT6/PE6
9  CLKO/PCINT7/PE7
10  !SS!/PCINT8/PB0
11  SCK/PCINT9/PB1
12  MOSI/PCINT10/PB2
13  MISO/PCINT11/PB3
14  OC0A/PCINT12/PB4
15  OC1B/PCINT14/PB6
16  OC1A/PCINT13/PB5
17  OC2A/PCINT15/PB7
18  T1/PG3
19  T0/PG4
20  !RESET!/PG5  in
21  VCC  pwr
22  GND  pwr
23  TOSC2/XTAL2  out
24  TOSC1/XTAL1  in
25  ICP1/PD0
26  INT0/PD1
27  PD2
28  PD3
29  PD4
30  PD5
31  PD6
32  PD7
33  PG0
34  PG1
35  PC0
36  PC1
37  PC2
38  PC3
39  PC4
40  PC5
41  PC6
42  PC7
43  PG2
44  PA7
45  PA6
46  PA5
47  PA4
48  PA3
49  PA2
50  PA1
51  PA0
52  VCC  pwr
53  GND  pwr
54  ADC7/TDI/PF7
55  ADC6/TDO/PF6
56  ADC5/TMS/PF5
57  ADC4/TCK/PF4
58  ADC3/PF3
59  ADC2/PF2
60  ADC1/PF1
61  ADC0/PF0
62  AREF  in
63  GND  pwr
64  AVCC  pwr

## Footprint 64M1 (pad centres in mm)
64M1 64-pad, 9 x 9 x 1.0 mm Lead Pitch 0.50 mm, 5.40 mm Exposed Pad, Micro Lead Frame Package (MLF) Source: http://www.atmel.com .. doc8023.pdf
smd 0.95 x 0.3: 1 -4.56,3.75; 2 -4.56,3.25; 3 -4.56,2.75; 4 -4.56,2.25; 5 -4.56,1.75; 6 -4.56,1.25; 7 -4.56,0.75; 8 -4.56,0.25; 9 -4.56,-0.25; 10 -4.56,-0.75; 11 -4.56,-1.25; 12 -4.56,-1.75; 13 -4.56,-2.25; 14 -4.56,-2.75; 15 -4.56,-3.25; 16 -4.56,-3.75; 33 4.56,-3.75; 34 4.56,-3.25; 35 4.56,-2.75; 36 4.56,-2.25; 37 4.56,-1.75; 38 4.56,-1.25; 39 4.56,-0.75; 40 4.56,-0.25; 41 4.56,0.25; 42 4.56,0.75; 43 4.56,1.25; 44 4.56,1.75; 45 4.56,2.25; 46 4.56,2.75; 47 4.56,3.25; 48 4.56,3.75
smd 0.3 x 0.95: 17 -3.75,-4.56; 18 -3.25,-4.56; 19 -2.75,-4.56; 20 -2.25,-4.56; 21 -1.75,-4.56; 22 -1.25,-4.56; 23 -0.75,-4.56; 24 -0.25,-4.56; 25 0.25,-4.56; 26 0.75,-4.56; 27 1.25,-4.56; 28 1.75,-4.56; 29 2.25,-4.56; 30 2.75,-4.56; 31 3.25,-4.56; 32 3.75,-4.56; 49 3.75,4.56; 50 3.25,4.56; 51 2.75,4.56; 52 2.25,4.56; 53 1.75,4.56; 54 1.25,4.56; 55 0.75,4.56; 56 0.25,4.56; 57 -0.25,4.56; 58 -0.75,4.56; 59 -1.25,4.56; 60 -1.75,4.56; 61 -2.25,4.56; 62 -2.75,4.56; 63 -3.25,4.56; 64 -3.75,4.56
smd 5.6 x 5.6: EXP 0,0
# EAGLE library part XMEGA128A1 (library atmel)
MICROCONTROLLER Features High-performance, Low-power 8/16-bit AVR XMEGA Microcontroller Non-Volatile Program and Data Memories - 64K - 384K Bytes of In-System Self-Programmable Flash - 4K - 8K Bytes Boot Section with Independent Lock Bits - 2 KB - 4 KB EEPROM - 4 KB - 32 KB Internal SRAM External Bus Interface for up to 16M bytes SRAM External Bus Interface for up to 128M bit SDRAM Peripheral Features - Four-channel DMA Controller with support for external requests - Eight-channel Event System - Eight 16-bit Timer/Counters Four Timer/Counters with 4 Output Compare or Input Capture channels Four Timer/Counters with 2 Output Compare or Input Capture channels High-Resolution Extension on all Timer/Counters Advanced Waveform Extension on two Timer/Counters - Eight USARTs IrDA modulation/demodulation for one USART - Four Two-Wire Interfaces with dual address match (I2C and SMBus compatible) - Four SPI (Serial Peripheral Interface) peripherals - AES and DES Crypto Engine - 16-bit Real Time Counter with separate Oscillator - Two Eight-channel, 12-bit, 2 Msps Analog to Digital Converters - Two Two-channel, 12-bit, 1 Msps Digital to Analog Converters - Four Analog Comparators with Window compare function - External Interrupts on all General Purpose I/O pins - Programmable Watchdog Timer with Separate On-chip Ultra Low Power Oscillator Special Microcontroller Features - Power-on Reset and Programmable Brown-out Detection - Internal and External Clock Options with PLL and Prescaler -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

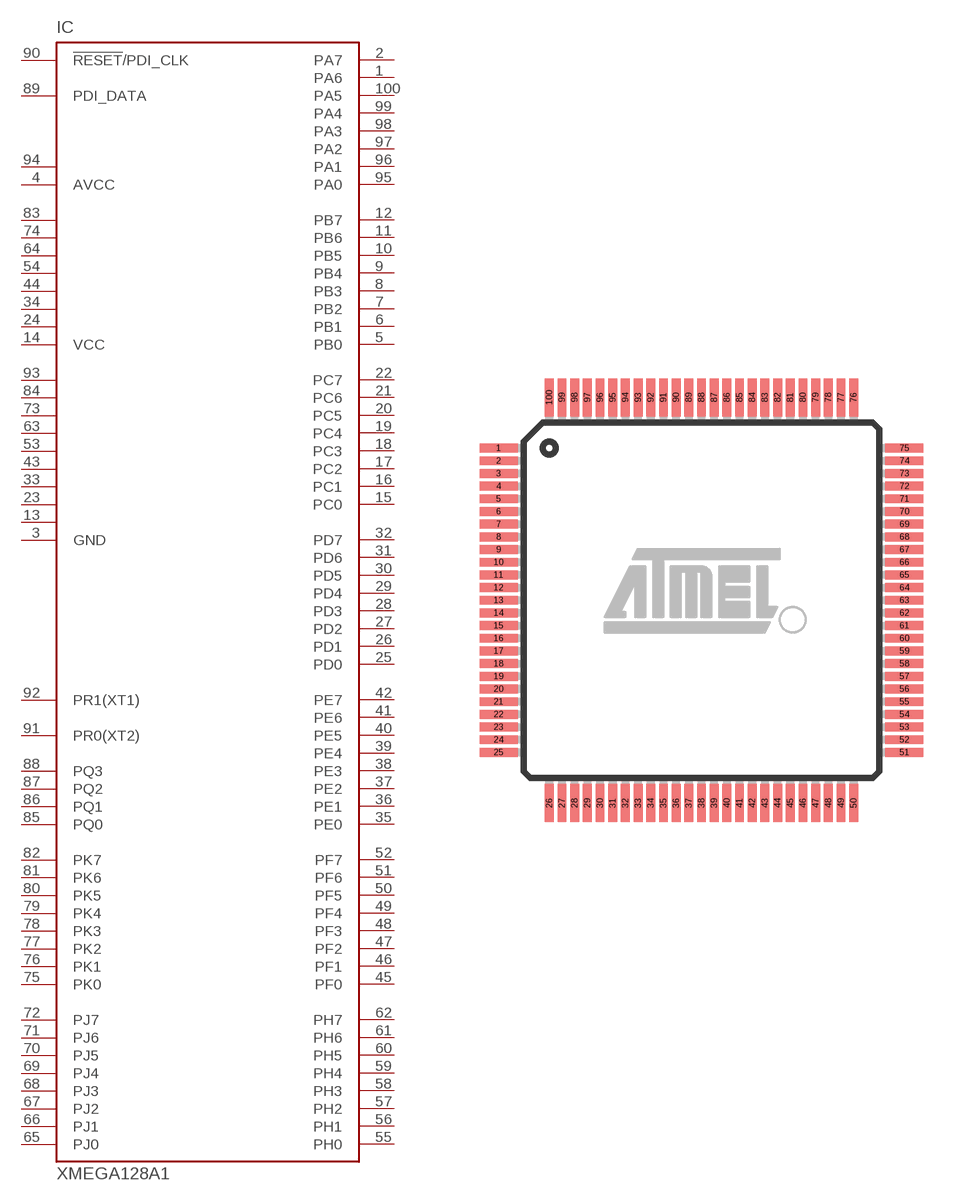
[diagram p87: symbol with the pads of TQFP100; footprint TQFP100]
Designator prefix IC

## XMEGA128A1 (OC_FARNELL: unknown; OC_NEWARK: unknown)  [TQFP100]
1  PA6
2  PA7
3  GND  pwr
4  AVCC  pwr
5  PB0
6  PB1
7  PB2
8  PB3
9  PB4
10  PB5
11  PB6
12  PB7
13  GND1  pwr
14  VCC  pwr
15  PC0
16  PC1
17  PC2
18  PC3
19  PC4
20  PC5
21  PC6
22  PC7
23  GND2  pwr
24  VCC1  pwr
25  PD0
26  PD1
27  PD2
28  PD3
29  PD4
30  PD5
31  PD6
32  PD7
33  GND3  pwr
34  VCC2  pwr
35  PE0
36  PE1
37  PE2
38  PE3
39  PE4
40  PE5
41  PE6
42  PE7
43  GND4  pwr
44  VCC3  pwr
45  PF0
46  PF1
47  PF2
48  PF3
49  PF4
50  PF5
51  PF6
52  PF7
53  GND5  pwr
54  VCC4  pwr
55  PH0
56  PH1
57  PH2
58  PH3
59  PH4
60  PH5
61  PH6
62  PH7
63  GND6  pwr
64  VCC5  pwr
65  PJ0
66  PJ1
67  PJ2
68  PJ3
69  PJ4
70  PJ5
71  PJ6
72  PJ7
73  GND7  pwr
74  VCC6  pwr
75  PK0
76  PK1
77  PK2
78  PK3
79  PK4
80  PK5
81  PK6
82  PK7
83  VCC7  pwr
84  GND8  pwr
85  PQ0
86  PQ1
87  PQ2
88  PQ3
89  PDI_DATA
90  !RESET!/PDI_CLK  in
91  PR0(XT2)
92  PR1(XT1)
93  GND9  pwr
94  AVCC1  pwr
95  PA0
96  PA1
97  PA2
98  PA3
99  PA4
100  PA5

## Footprint TQFP100 (pad centres in mm)
100-lead Thin Quad Flat Pack Package
smd 1.5 x 0.35: 1 -8,6; 2 -8,5.5; 3 -8,5; 4 -8,4.5; 5 -8,4; 6 -8,3.5; 7 -8,3; 8 -8,2.5; 9 -8,2; 10 -8,1.5; 11 -8,1; 12 -8,0.5; 13 -8,0; 14 -8,-0.5; 15 -8,-1; 16 -8,-1.5; 17 -8,-2; 18 -8,-2.5; 19 -8,-3; 20 -8,-3.5; 21 -8,-4; 22 -8,-4.5; 23 -8,-5; 24 -8,-5.5; 25 -8,-6; 51 8,-6; 52 8,-5.5; 53 8,-5; 54 8,-4.5; 55 8,-4; 56 8,-3.5; 57 8,-3; 58 8,-2.5; 59 8,-2; 60 8,-1.5; 61 8,-1; 62 8,-0.5; 63 8,0; 64 8,0.5; 65 8,1; 66 8,1.5; 67 8,2; 68 8,2.5; 69 8,3; 70 8,3.5; 71 8,4; 72 8,4.5; 73 8,5; 74 8,5.5; 75 8,6
smd 0.35 x 1.5: 26 -6,-8; 27 -5.5,-8; 28 -5,-8; 29 -4.5,-8; 30 -4,-8; 31 -3.5,-8; 32 -3,-8; 33 -2.5,-8; 34 -2,-8; 35 -1.5,-8; 36 -1,-8; 37 -0.5,-8; 38 0,-8; 39 0.5,-8; 40 1,-8; 41 1.5,-8; 42 2,-8; 43 2.5,-8; 44 3,-8; 45 3.5,-8; 46 4,-8; 47 4.5,-8; 48 5,-8; 49 5.5,-8; 50 6,-8; 76 6,8; 77 5.5,8; 78 5,8; 79 4.5,8; 80 4,8; 81 3.5,8; 82 3,8; 83 2.5,8; 84 2,8; 85 1.5,8; 86 1,8; 87 0.5,8; 88 0,8; 89 -0.5,8; 90 -1,8; 91 -1.5,8; 92 -2,8; 93 -2.5,8; 94 -3,8; 95 -3.5,8; 96 -4,8; 97 -4.5,8; 98 -5,8; 99 -5.5,8; 100 -6,8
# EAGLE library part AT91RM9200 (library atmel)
Auto generated by make-symbol-device-package(bsdl).ulp Source: at91rm9200_bga.bsd

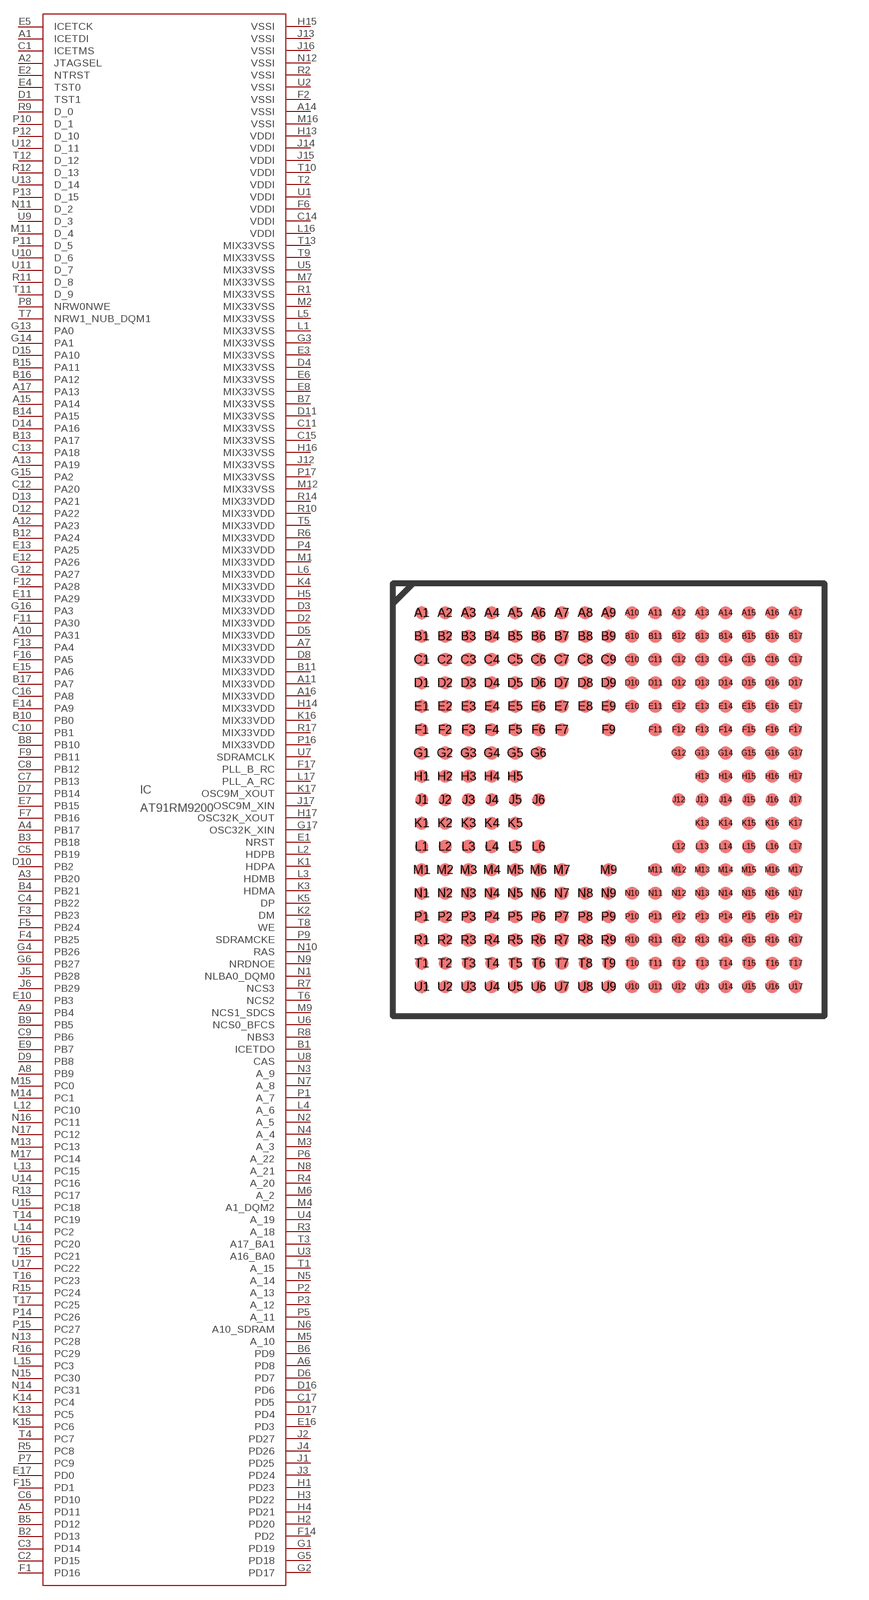
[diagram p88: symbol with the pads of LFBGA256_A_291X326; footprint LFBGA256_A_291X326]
Designator prefix IC

## AT91RM9200 (MPN: AT91RM9200-EK; OC_FARNELL: 1629536; OC_NEWARK: 02P6234)  [LFBGA256_A_291X326]
A1  ICETDI  in
A2  JTAGSEL  in
A3  PB20
A4  PB17
A5  PD11
A6  PD8
A7  MIX33VDD  pwr
A8  PB9
A9  PB4
A10  PA31
A11  MIX33VDD  pwr
A12  PA23
A13  PA19
A14  VSSI  pwr
A15  PA14
A16  MIX33VDD  pwr
A17  PA13
B1  ICETDO  out
B2  PD13
B3  PB18
B4  PB21
B5  PD12
B6  PD9
B7  MIX33VSS  pwr
B8  PB10
B9  PB5
B10  PB0
B11  MIX33VDD  pwr
B12  PA24
B13  PA17
B14  PA15
B15  PA11
B16  PA12
B17  PA7
C1  ICETMS  in
C2  PD15
C3  PD14
C4  PB22
C5  PB19
C6  PD10
C7  PB13
C8  PB12
C9  PB6
C10  PB1
C11  MIX33VSS  pwr
C12  PA20
C13  PA18
C14  VDDI  pwr
C15  MIX33VSS  pwr
C16  PA8
C17  PD5
D1  TST1  in
D2  MIX33VDD  pwr
D3  MIX33VDD  pwr
D4  MIX33VSS  pwr
D5  MIX33VDD  pwr
D6  PD7
D7  PB14
D8  MIX33VDD  pwr
D9  PB8
D10  PB2
D11  MIX33VSS  pwr
D12  PA22
D13  PA21
D14  PA16
D15  PA10
D16  PD6
D17  PD4
E1  NRST  pwr
E2  NTRST  in
E3  MIX33VSS  pwr
E4  TST0  in
E5  ICETCK  in
E6  MIX33VSS  pwr
E7  PB15
E8  MIX33VSS  pwr
E9  PB7
E10  PB3
E11  PA29
E12  PA26
E13  PA25
E14  PA9
E15  PA6
E16  PD3
E17  PD0
F1  PD16
F2  VSSI  pwr
F3  PB23
F4  PB25
F5  PB24
F6  VDDI  pwr
F7  PB16
F9  PB11
F11  PA30
F12  PA28
F13  PA4
F14  PD2
F15  PD1
F16  PA5
F17  PLL_B_RC  pwr
G1  PD19
G2  PD17
G3  MIX33VSS  pwr
G4  PB26
G5  PD18
G6  PB27
G12  PA27
G13  PA0
G14  PA1
G15  PA2
G16  PA3
G17  OSC32K_XIN  pwr
H1  PD23
H2  PD20
H3  PD22
H4  PD21
H5  MIX33VDD  pwr
H13  VDDI  pwr
H14  MIX33VDD  pwr
H15  VSSI  pwr
H16  MIX33VSS  pwr
H17  OSC32K_XOUT  pwr
J1  PD25
J2  PD27
J3  PD24
J4  PD26
J5  PB28
J6  PB29
J12  MIX33VSS  pwr
J13  VSSI  pwr
J14  VDDI  pwr
J15  VDDI  pwr
J16  VSSI  pwr
J17  OSC9M_XIN  pwr
K1  HDPA  pwr
K2  DM  pwr
K3  HDMA  pwr
K4  MIX33VDD  pwr
K5  DP  pwr
K13  PC5
K14  PC4
K15  PC6
K16  MIX33VDD  pwr
K17  OSC9M_XOUT  pwr
L1  MIX33VSS  pwr
L2  HDPB  pwr
L3  HDMB  pwr
L4  A_6  out
L5  MIX33VSS  pwr
L6  MIX33VDD  pwr
L12  PC10
L13  PC15
L14  PC2
L15  PC3
L16  VDDI  pwr
L17  PLL_A_RC  pwr
M1  MIX33VDD  pwr
M2  MIX33VSS  pwr
M3  A_3  out
M4  A1_DQM2  out
M5  A_10  out
M6  A_2  out
M7  MIX33VSS  pwr
M9  NCS1_SDCS  out
M11  D_4
M12  MIX33VSS  pwr
M13  PC13
M14  PC1
M15  PC0
M16  VSSI  pwr
M17  PC14
N1  NLBA0_DQM0  out
N2  A_5  out
N3  A_9  out
N4  A_4  out
N5  A_14  out
N6  A10_SDRAM  out
N7  A_8  out
N8  A_21  out
N9  NRDNOE  out
N10  RAS  out
N11  D_2
N12  VSSI  pwr
N13  PC28
N14  PC31
N15  PC30
N16  PC11
N17  PC12
P1  A_7  out
P2  A_13  out
P3  A_12  out
P4  MIX33VDD  pwr
P5  A_11  out
P6  A_22  out
P7  PC9
P8  NRW0NWE
P9  SDRAMCKE  out
P10  D_1
P11  D_5
P12  D_10
P13  D_15
P14  PC26
P15  PC27
P16  MIX33VDD  pwr
P17  MIX33VSS  pwr
R1  MIX33VSS  pwr
R2  VSSI  pwr
R3  A_18  out
R4  A_20  out
R5  PC8
R6  MIX33VDD  pwr
R7  NCS3  out
R8  NBS3  out
R9  D_0
R10  MIX33VDD  pwr
R11  D_8
R12  D_13
R13  PC17
R14  MIX33VDD  pwr
R15  PC24
R16  PC29
R17  MIX33VDD  pwr
T1  A_15  out
T2  VDDI  pwr
T3  A17_BA1  out
T4  PC7
T5  MIX33VDD  pwr
T6  NCS2  out
T7  NRW1_NUB_DQM1
T8  WE  out
T9  MIX33VSS  pwr
T10  VDDI  pwr
T11  D_9
T12  D_12
T13  MIX33VSS  pwr
T14  PC19
T15  PC21
T16  PC23
T17  PC25
U1  VDDI  pwr
U2  VSSI  pwr
U3  A16_BA0  out
U4  A_19  out
U5  MIX33VSS  pwr
U6  NCS0_BFCS  out
U7  SDRAMCLK  pwr
U8  CAS  out
U9  D_3
U10  D_6
U11  D_7
U12  D_11
U13  D_14
U14  PC16
U15  PC18
U16  PC20
U17  PC22

## Footprint LFBGA256_A_291X326 (pad centres in mm)
Auto generated by make-symbol-device-package(bsdl).ulp Source: at91rm9200_bga.bsd
smd 0.45 x 0.45: A1 -6.4,6.4; A2 -5.6,6.4; A3 -4.8,6.4; A4 -4,6.4; A5 -3.2,6.4; A6 -2.4,6.4; A7 -1.6,6.4; A8 -0.8,6.4; A9 0,6.4; A10 0.8,6.4; A11 1.6,6.4; A12 2.4,6.4; A13 3.2,6.4; A14 4,6.4; A15 4.8,6.4; A16 5.6,6.4; A17 6.4,6.4; B1 -6.4,5.6; B2 -5.6,5.6; B3 -4.8,5.6; B4 -4,5.6; B5 -3.2,5.6; B6 -2.4,5.6; B7 -1.6,5.6; B8 -0.8,5.6; B9 0,5.6; B10 0.8,5.6; B11 1.6,5.6; B12 2.4,5.6; B13 3.2,5.6; B14 4,5.6; B15 4.8,5.6; B16 5.6,5.6; B17 6.4,5.6; C1 -6.4,4.8; C2 -5.6,4.8; C3 -4.8,4.8; C4 -4,4.8; C5 -3.2,4.8; C6 -2.4,4.8; C7 -1.6,4.8; C8 -0.8,4.8; C9 0,4.8; C10 0.8,4.8; C11 1.6,4.8; C12 2.4,4.8; C13 3.2,4.8; C14 4,4.8; C15 4.8,4.8; C16 5.6,4.8; C17 6.4,4.8; D1 -6.4,4; D2 -5.6,4; D3 -4.8,4; D4 -4,4; D5 -3.2,4; D6 -2.4,4; D7 -1.6,4; D8 -0.8,4; D9 0,4; D10 0.8,4; D11 1.6,4; D12 2.4,4; D13 3.2,4; D14 4,4; D15 4.8,4; D16 5.6,4; D17 6.4,4; E1 -6.4,3.2; E2 -5.6,3.2; E3 -4.8,3.2; E4 -4,3.2; E5 -3.2,3.2; E6 -2.4,3.2; E7 -1.6,3.2; E8 -0.8,3.2; E9 0,3.2; E10 0.8,3.2; E11 1.6,3.2; E12 2.4,3.2; E13 3.2,3.2; E14 4,3.2; E15 4.8,3.2; E16 5.6,3.2; E17 6.4,3.2; F1 -6.4,2.4; F2 -5.6,2.4; F3 -4.8,2.4; F4 -4,2.4; F5 -3.2,2.4; F6 -2.4,2.4; F7 -1.6,2.4; F9 0,2.4; F11 1.6,2.4; F12 2.4,2.4; F13 3.2,2.4; F14 4,2.4; F15 4.8,2.4; F16 5.6,2.4; F17 6.4,2.4; G1 -6.4,1.6; G2 -5.6,1.6; G3 -4.8,1.6; G4 -4,1.6; G5 -3.2,1.6; G6 -2.4,1.6; G12 2.4,1.6; G13 3.2,1.6; G14 4,1.6; G15 4.8,1.6; G16 5.6,1.6; G17 6.4,1.6; H1 -6.4,0.8; H2 -5.6,0.8; H3 -4.8,0.8; H4 -4,0.8; H5 -3.2,0.8; H13 3.2,0.8; H14 4,0.8; H15 4.8,0.8; H16 5.6,0.8; H17 6.4,0.8; J1 -6.4,0; J2 -5.6,0; J3 -4.8,0; J4 -4,0; J5 -3.2,0; J6 -2.4,0; J12 2.4,0; J13 3.2,0; J14 4,0; J15 4.8,0; J16 5.6,0; J17 6.4,0; K1 -6.4,-0.8; K2 -5.6,-0.8; K3 -4.8,-0.8; K4 -4,-0.8; K5 -3.2,-0.8; K13 3.2,-0.8; K14 4,-0.8; K15 4.8,-0.8; K16 5.6,-0.8; K17 6.4,-0.8; L1 -6.4,-1.6; L2 -5.6,-1.6; L3 -4.8,-1.6; L4 -4,-1.6; L5 -3.2,-1.6; L6 -2.4,-1.6; L12 2.4,-1.6; L13 3.2,-1.6; L14 4,-1.6; L15 4.8,-1.6; L16 5.6,-1.6; L17 6.4,-1.6; M1 -6.4,-2.4; M2 -5.6,-2.4; M3 -4.8,-2.4; M4 -4,-2.4; M5 -3.2,-2.4; M6 -2.4,-2.4; M7 -1.6,-2.4; M9 0,-2.4; M11 1.6,-2.4; M12 2.4,-2.4; M13 3.2,-2.4; M14 4,-2.4; M15 4.8,-2.4; M16 5.6,-2.4; M17 6.4,-2.4; N1 -6.4,-3.2; N2 -5.6,-3.2; N3 -4.8,-3.2; N4 -4,-3.2; N5 -3.2,-3.2; N6 -2.4,-3.2; N7 -1.6,-3.2; N8 -0.8,-3.2; N9 0,-3.2; N10 0.8,-3.2; N11 1.6,-3.2; N12 2.4,-3.2; N13 3.2,-3.2; N14 4,-3.2; N15 4.8,-3.2; N16 5.6,-3.2; N17 6.4,-3.2; P1 -6.4,-4; P2 -5.6,-4; P3 -4.8,-4; P4 -4,-4; P5 -3.2,-4; P6 -2.4,-4; P7 -1.6,-4; P8 -0.8,-4; P9 0,-4; P10 0.8,-4; P11 1.6,-4; P12 2.4,-4; P13 3.2,-4; P14 4,-4; P15 4.8,-4; P16 5.6,-4; P17 6.4,-4; R1 -6.4,-4.8; R2 -5.6,-4.8; R3 -4.8,-4.8; R4 -4,-4.8; R5 -3.2,-4.8; R6 -2.4,-4.8; R7 -1.6,-4.8; R8 -0.8,-4.8; R9 0,-4.8; R10 0.8,-4.8; R11 1.6,-4.8; R12 2.4,-4.8; R13 3.2,-4.8; R14 4,-4.8; R15 4.8,-4.8; R16 5.6,-4.8; R17 6.4,-4.8; T1 -6.4,-5.6; T2 -5.6,-5.6; T3 -4.8,-5.6; T4 -4,-5.6; T5 -3.2,-5.6; T6 -2.4,-5.6; T7 -1.6,-5.6; T8 -0.8,-5.6; T9 0,-5.6; T10 0.8,-5.6; T11 1.6,-5.6; T12 2.4,-5.6; T13 3.2,-5.6; T14 4,-5.6; T15 4.8,-5.6; T16 5.6,-5.6; T17 6.4,-5.6; U1 -6.4,-6.4; U2 -5.6,-6.4; U3 -4.8,-6.4; U4 -4,-6.4; U5 -3.2,-6.4; U6 -2.4,-6.4; U7 -1.6,-6.4; U8 -0.8,-6.4; U9 0,-6.4; U10 0.8,-6.4; U11 1.6,-6.4; U12 2.4,-6.4; U13 3.2,-6.4; U14 4,-6.4; U15 4.8,-6.4; U16 5.6,-6.4; U17 6.4,-6.4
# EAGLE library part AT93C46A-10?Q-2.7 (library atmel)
Three-wire Automotive Temperature Serial EEPROM 1K (64 x 16) Source: http://www.atmel.com/dyn/resources/prod_documents/doc5089.pdf

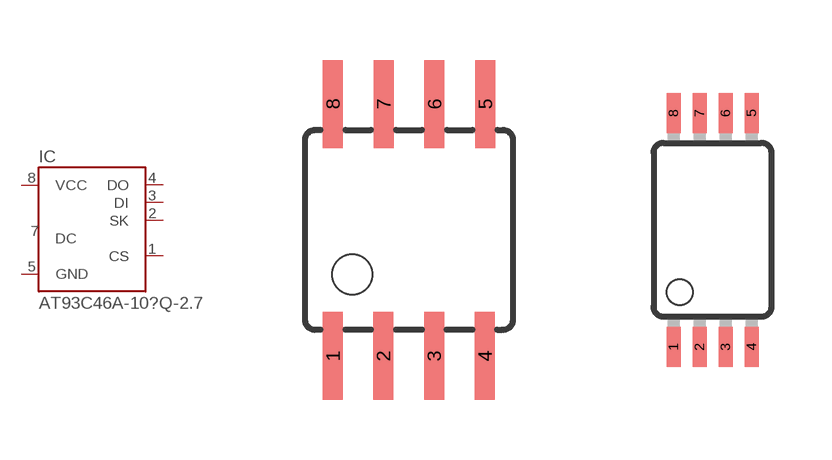
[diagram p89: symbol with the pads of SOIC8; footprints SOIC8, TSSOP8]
Designator prefix IC

## AT93C46A-10SQ-2.7 (MPN: AT93C46DN-SH-B; OC_FARNELL: 1455086; OC_NEWARK: 58M3879)  [SOIC8]
1  CS  in
2  SK  in
3  DI  in
4  DO  out
5  GND  pwr
6  NC  nc
7  DC  nc
8  VCC  pwr

## AT93C46A-10TQ-2.7 (OC_FARNELL: unknown; OC_NEWARK: unknown)  [TSSOP8]
Pads as for SOIC8

## Footprint SOIC8 (pad centres in mm)
Wide Plastic Gull Wing Small Outline Package
smd 0.5 x 2.2: 1 -1.905,-3.154; 2 -0.645,-3.154; 3 0.625,-3.154; 4 1.895,-3.154; 5 1.905,3.154; 6 0.635,3.154; 7 -0.635,3.154; 8 -1.905,3.154

## Footprint TSSOP8 (pad centres in mm)
8A2-TSSOP Source: http://www.atmel.com/dyn/resources/prod_documents/doc5089.pdf
smd 0.35 x 1: 1 -0.975,-2.925; 2 -0.325,-2.925; 3 0.325,-2.925; 4 0.975,-2.925; 5 0.975,2.925; 6 0.325,2.925; 7 -0.325,2.925; 8 -0.975,2.925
